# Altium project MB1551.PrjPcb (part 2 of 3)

## Sheet MEMs.SchDoc: MEMs
size A4; Date: Not used; ApprovedBy: Not used; CheckedBy: Not used; Author: Not used; CompanyName: STMicroelectronics; DrawnBy: Not used; Engineer: Not used; Organization: Not used; Address1: Not used; Address2: Not used; Address3: Not used; Address4: Not used; DocumentNumber: 12; Revision: Not used; SheetNumber: 12; SheetTotal: 16

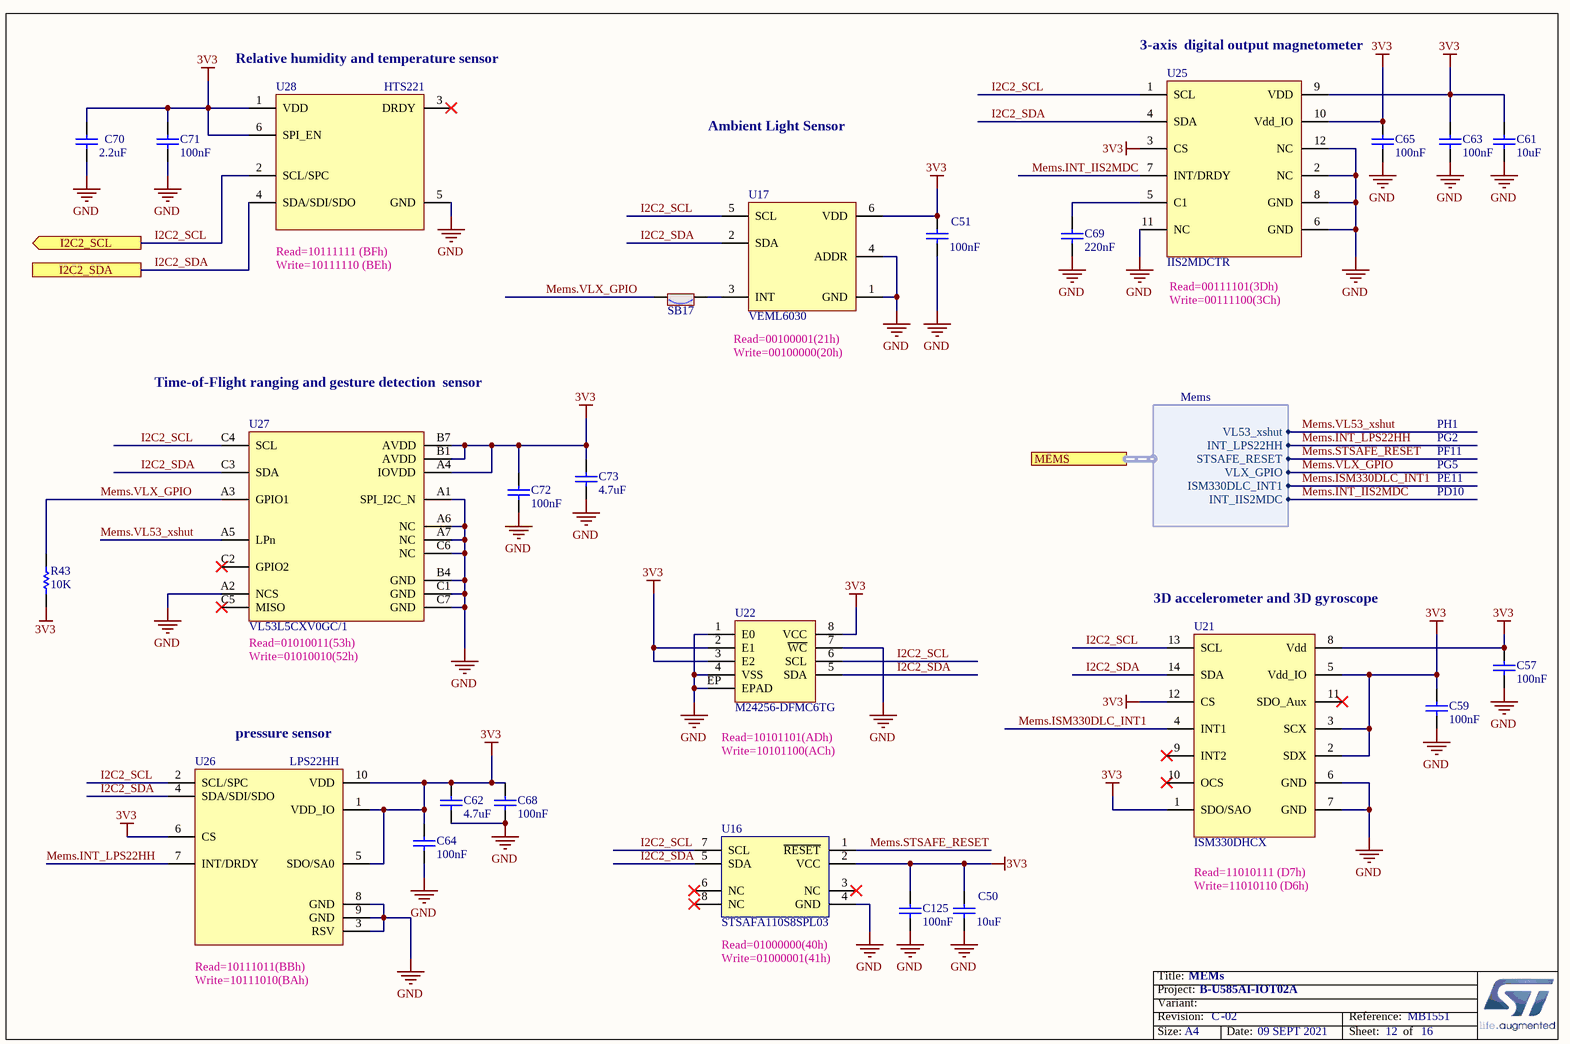
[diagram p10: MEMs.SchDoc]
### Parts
C50  value 10uF  [C0402]  (hidden comment: Capacitor)
C51  value 100nF  [C0402]
C57  value 100nF  [C0402]
C59  value 100nF  [C0402]
C61  value 10uF  [C0603]  (hidden comment: Capacitor)
C62  value 4.7uF  [C0603]  (hidden comment: Capacitor)
C63  value 100nF  [C0402]
C64  value 100nF  [C0402]
C65  value 100nF  [C0402]
C68  value 100nF  [C0402]
C69  value 220nF  [C0402]  (hidden comment: Capacitor)
C70  value 2.2uF  [C0603_H0P8]  (hidden comment: Capacitor)
C71  value 100nF  [C0402]
C72  value 100nF  [C0402]
C73  value 4.7uF  [C0603]  (hidden comment: Capacitor)
C125  value 100nF  [C0402]
R43  value 10K  [R0402]  (hidden comment: Resistor)
SB17  (no value)  [SOLDER-BRIDGE_R0603-0R]
U16  value STSAFA110S8SPL03  [ICC_SO8_5X4_P127]  (hidden comment: STSAFA110S8)
U17  VEML6030  [ICC_VISHAY_VEML6030_2X2_P065]
U21  ISM330DHCX  [ICC_LGA14_3X2P5_P050]
U22  value M24256-DFMC6TG  [ICC_DFN8-EPAD_2X3_P050]  (hidden comment: M24128-DFMC6TP)
U25  IIS2MDCTR  [ICC_LGA12_2X2_P050_H0P7]
U26  LPS22HH  [ICC_HLGA10_2X2_P050]
U27  value VL53L5CXV0GC/1  [ICC_LGA16_6P4X3_P075_H1P5]  (hidden comment: VL53L5CAV0GC)
U28  HTS221  [ICC_HLGA6_2X2_P075-1]

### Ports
I2C2_SCL (out), I2C2_SDA, MEMS (harness Mems)

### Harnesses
Mems: INT_LPS22HH, VLX_GPIO, ISM330DLC_INT1, INT_IIS2MDC, STSAFE_RESET, VL53_xshut

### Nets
3V3: C50.2 C51.1 C57.1 C59.1 C61.2 C62.2 C63.1 C64.1 C65.1 C68.1 C70.2 C71.1 C72.1 C73.2 C125.1 R43.2 U16.2(VCC) U17.6(VDD) U21.1(SDO/SAO) U21.2(SDX) U21.3(SCX) U21.5(Vdd_IO) U21.8(Vdd) U21.12(CS) U22.2(E1) U22.3(E2) U22.8(VCC) U25.3(CS) U25.9(VDD) U25.10(Vdd_IO) U26.1(VDD_IO) U26.5(SDO/SA0) U26.6(CS) U26.10(VDD) U27.A4(IOVDD) U27.B1(AVDD) U27.B7(AVDD) U28.1(VDD) U28.6(SPI_EN)
GND: C50.1 C51.2 C57.2 C59.2 C61.1 C62.1 C63.2 C64.2 C65.2 C68.2 C69.1 C70.1 C71.2 C72.2 C73.1 C125.2 U16.4(GND) U17.1(GND) U17.4(ADDR) U21.6(GND) U21.7(GND) U22.1(E0) U22.4(VSS) U22.7(~{WC}) U22.EP(EPAD) U25.2(NC) U25.6(GND) U25.8(GND) U25.11(NC) U25.12(NC) U26.3(RSV) U26.8(GND) U26.9(GND) U27.A1(SPI_I2C_N) U27.A2(NCS) U27.A6(NC) U27.A7(NC) U27.B4(GND) U27.C1(GND) U27.C6(NC) U27.C7(GND) U28.5(GND)
I2C2_SCL: U16.7(SCL) U17.5(SCL) U21.13(SCL) U22.6(SCL) U25.1(SCL) U26.2(SCL/SPC) U27.C4(SCL) U28.2(SCL/SPC) ; port I2C2_SCL
I2C2_SDA: U16.5(SDA) U17.2(SDA) U21.14(SDA) U22.5(SDA) U25.4(SDA) U26.4(SDA/SDI/SDO) U27.C3(SDA) U28.4(SDA/SDI/SDO) ; port I2C2_SDA
Mems.INT_IIS2MDC: U25.7(INT/DRDY) ; port MEMS.INT_IIS2MDC
Mems.INT_LPS22HH: U26.7(INT/DRDY) ; port MEMS.INT_LPS22HH
Mems.ISM330DLC_INT1: U21.4(INT1) ; port MEMS.ISM330DLC_INT1
Mems.STSAFE_RESET: U16.1(~{RESET}) ; port MEMS.STSAFE_RESET
Mems.VL53_xshut: U27.A5(LPn) ; port MEMS.VL53_xshut
Mems.VLX_GPIO: R43.1 SB17.2 U27.A3(GPIO1) ; port MEMS.VLX_GPIO
NetC69_2: C69.2 U25.5(C1)
NetSB17_1: SB17.1 U17.3(INT)

Not connected (* = marked no-connect by the designer): U16 3(NC)* 6(NC)* 8(NC)*; U21 9(INT2)* 10(OCS)* 11(SDO_Aux)*; U27 C2(GPIO2)* C5(MISO)*; U28 3(DRDY)*

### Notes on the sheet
- (near U25) 3-axis  digital output magnetometer
- (near U28) Relative humidity and temperature sensor
- Ambient Light Sensor
- (near U28) Read=10111111 (BFh)
  Write=10111110 (BEh)
- (near U25) Read=00111101(3Dh)
  Write=00111100(3Ch)
- Time-of-Flight ranging and gesture detection  sensor
- Read=00100001(21h)
  Write=00100000(20h)
- PG2
- PF11
- PH1
- PE11
- PD10
- PG5
- (near U27) Read=01010011(53h)
  Write=01010010(52h)
- (near U21) 3D accelerometer and 3D gyroscope
- (near U26) pressure sensor
- (near U22) Read=10101101(ADh)
  Write=10101100(ACh)
- Read=11010111 (D7h)
  Write=11010110 (D6h)
- (near U26) Read=10111011(BBh)
  Write=10111010(BAh)
- Read=01000000(40h)
  Write=01000001(41h)

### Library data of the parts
C50 = MCD-01716: Capacitor, MLCC, 10uF, 6V3, X5R, +/-20%, 0402, T=0.5mm; Part_Preference: Recommended; Manufacturer: YAGEO; Manufacturer_Part_Number: CC0402MRX5R5BB106
C51 C57 C59 C63-C65 C68 C71 C72 C125 = MCD-00006: Capacitor, MLCC, 100nF, 16V, X7R, 10%, 0402, T=0.5mm; Manufacturer_Part_Number: CC0402KRX7R7BB104; Manufacturer: YAGEO; Provided_By: Subcon; Initial_Board_Reference: MB1274
C61 = MCD-01124: Capacitor, MLCC, 10µF, 10V, X5R, 10%, 0603, T=0.8mm; Manufacturer_Part_Number: GRM188R61A106KAAL; Manufacturer: MURATA; Provided_By: SUBCO
C62 C73 = MCD-00009: Capacitor, MLCC, 4.7uF, 16V, X5R, 10%, 0603, T=0.8mm; Manufacturer_Part_Number: CC0603KRX5R7BB475; Manufacturer: YAGEO; Provided_By: subcon; Initial_Board_Reference: MB1274
C69 = MCD-00602: Capacitor, MLCC, 220nF, 16V, 0402, X7R, 10%, T=0,5mm; Manufacturer_Part_Number: GRM155R71C223KA01J; Manufacturer: MURATA; Provided_By: SUBCO
C70 = MCD-01540: Capacitor,X5R,2.2uF, 15%, 50V, 0603; Manufacturer_Part_Number: GRM188R61H225KE11; Manufacturer: MURATA; Provided_By: SUBCO
R43 = MCD-00053: Resistor,10K,0402,1%,1/16W; Manufacturer_Part_Number: RC0402FR-0710KL; Manufacturer: YAGEO; Provided_By: SUBCO
SB17 = MCD-00071: Solder Bridge ON; Part_Type: Mechanical; Provided_By: Subcon; Initial_Board_Reference: mb1274
U16 = MCD-02399: Authentication, state-of-the-art security for peripherals and IoT devices; Part_Type: IC; Part_Preference: Recommended; Manufacturer: STMICROELECTRONICS
U17 = MCD-02336: High Accuracy Ambient Light Sensor with I2C Interface; Part_Type: IC; Part_Preference: Recommended; Manufacturer: VISHAY
U21 = MCD-02160: iNEMO inertial module: 3D accelerometer and 3D gyroscope, with digital output for industrial applications; Part_Preference: Recommended; Part_Type: IC; Manufacturer: STMICROELECTRONICS; Order_code_RS: ISM330DHCXTR; Component_Country_Of_Origin: Malta, Philippines
U22 = MCD-01871: I2C Memory 3V3, 256Kbits, 2x3,0.55mm, UFDFPN8; Part_Type: IC; Manufacturer: STMICROELECTRONICS; BMS_Part_Number: 9175665; Provided_By: SUBCO with ST control
U25 = MCD-01713: High-accuracy, ultra-low-power, 3-axis, digital output magnetometer; Part_Type: IC; Manufacturer: STMICROELECTRONICS; Provided_By: SUBCO with ST control
U26 = MCD-01702: High-performance MEMS nano pressure sensor:260-1260 hPa absolute digital output barometer; Part_Type: IC; Manufacturer: STMICROELECTRONICS; Provided_By: SUBCO
U27 = MCD-02257: Time-of-Flight mini depth camera; Part_Type: IC; Part_Preference: Recommended; Manufacturer: STMICROELECTRONICS; Manufacturer_HQ_COO: EU
U28 = MCD-01447: Capacitive digital sensor for relative humidity and temperature; Part_Type: IC; Manufacturer: STMICROELECTRONICS; BMS_Part_Number: 9188011; ECCN_US: EAR99; ECCN_EU: NEC; Provided_By: SUBCO

## Sheet OCTOSPI.SchDoc: OCTOSPI
size A4; Date: Not used; ApprovedBy: Not used; CheckedBy: Not used; Author: Not used; CompanyName: STMicroelectronics; DrawnBy: Not used; Engineer: Not used; Organization: Not used; Address1: Not used; Address2: Not used; Address3: Not used; Address4: Not used; DocumentNumber: 6; Revision: Not used; SheetNumber: 6; SheetTotal: 16

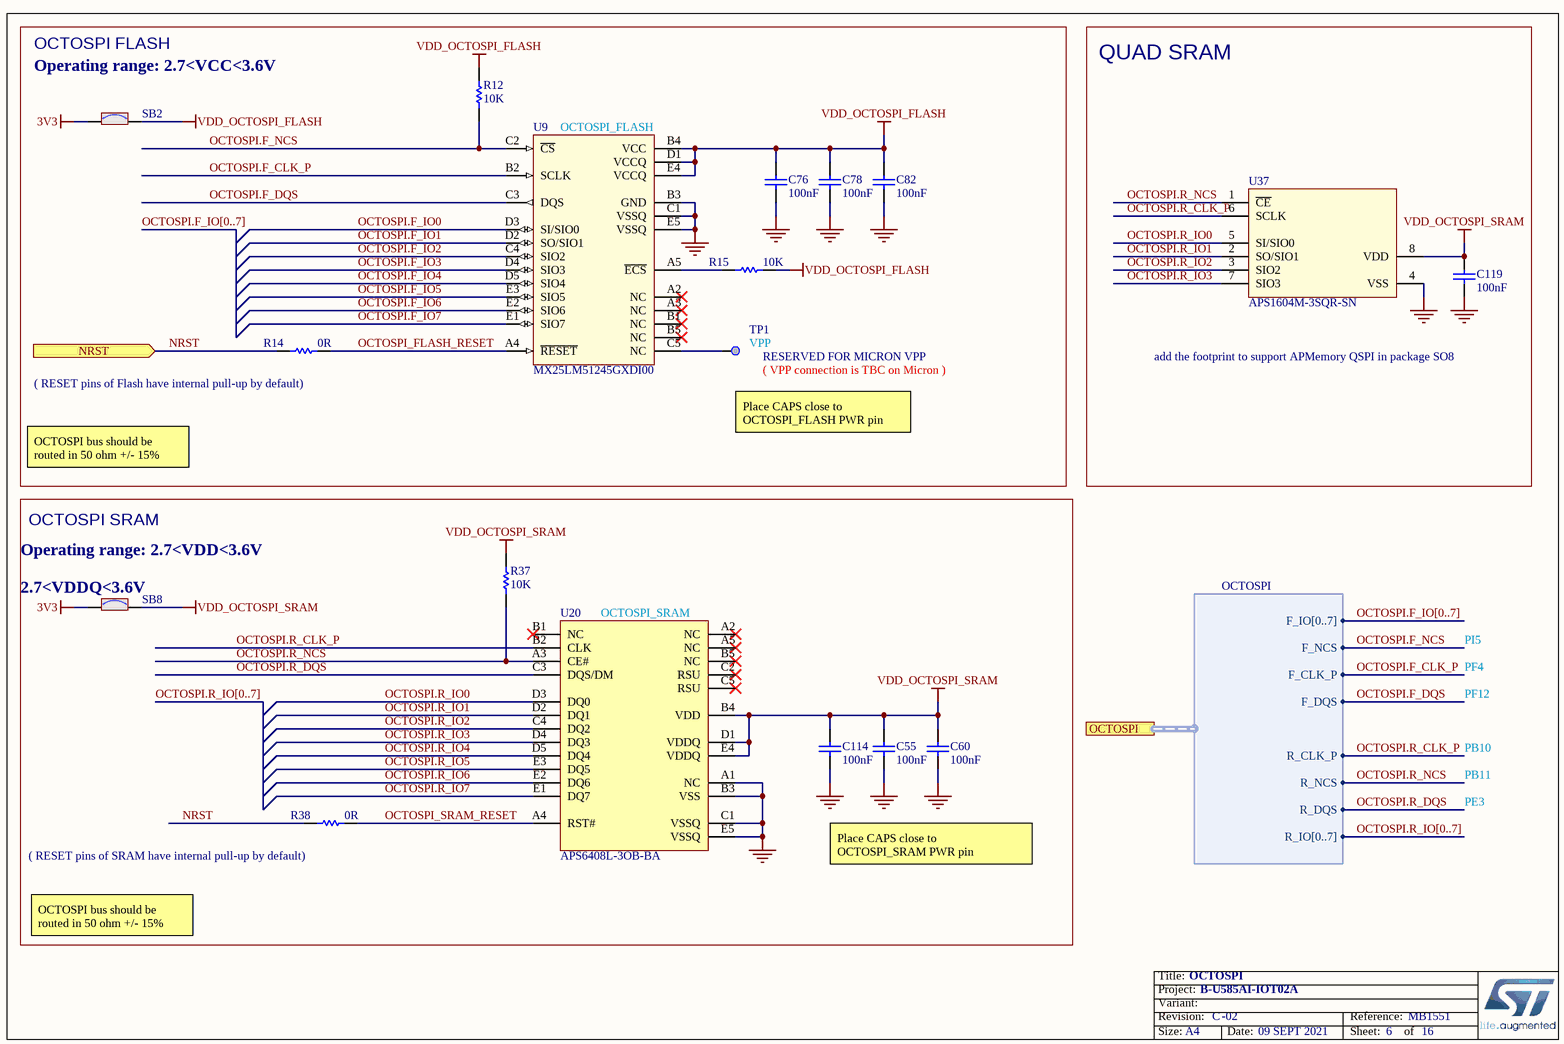
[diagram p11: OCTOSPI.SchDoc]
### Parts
C55  value 100nF  [C0402]
C60  value 100nF  [C0402]
C76  value 100nF  [C0402]
C78  value 100nF  [C0402]
C82  value 100nF  [C0402]
C114  value 100nF  [C0402]
C119  value 100nF  [C0402]  (hidden comment: Capacitor)
R12  value 10K  [R0603]
R14  value 0R  [R0603]
R15  value 10K  [R0603]
R37  value 10K  [R0603]
R38  value 0R  [R0603]
SB2  (no value)  [SOLDER-BRIDGE_R0603-0R]
SB8  (no value)  [SOLDER-BRIDGE_R0603-0R]
TP1  value VPP  [TP_SMD_1MM]  (no BOM)
U9  value MX25LM51245GXDI00  [ICC_BGA24_5X5-BALL-ARRAY_6X8_P1]
U20  value APS6408L-3OB-BA  [ICC_MINI-BGA24_6X8_P1]  (hidden comment: APS6408L-xOB)
U37  APS1604M-3SQR-SN  [ICC_SO8_5X4_P127]

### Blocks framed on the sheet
OCTOSPI FLASH: C76 C78 C82 R12 R14 R15 SB2 TP1 U9
QUAD SRAM: C119 U37
OCTOSPI SRAM: C55 C60 C114 R37 R38 SB8 U20

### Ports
NRST (in), OCTOSPI (harness OCTOSPI)

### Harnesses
OCTOSPI: F_DQS, F_CLK_P, F_NCS, R_CLK_P, R_NCS, R_DQS, R_IO[0..7], F_IO[0..7]

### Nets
3V3: SB2.1 SB8.1
GND: C55.1 C60.1 C76.1 C78.1 C82.1 C114.1 C119.1 U9.B3(GND) U9.C1(VSSQ) U9.E5(VSSQ) U20.A1(NC) U20.B3(VSS) U20.C1(VSSQ) U20.E5(VSSQ) U37.4(VSS)
VDD_OCTOSPI_FLASH: C76.2 C78.2 C82.2 R12.2 R15.1 SB2.2 U9.B4(VCC) U9.D1(VCCQ) U9.E4(VCCQ)
VDD_OCTOSPI_SRAM: C55.2 C60.2 C114.2 C119.2 R37.2 SB8.2 U20.B4(VDD) U20.D1(VDDQ) U20.E4(VDDQ) U37.8(VDD)
NRST: R14.1 R38.1 ; port NRST
OCTOSPI.F_CLK_P: U9.B2(SCLK) ; port OCTOSPI.F_CLK_P
OCTOSPI.F_DQS: U9.C3(DQS) ; port OCTOSPI.F_DQS
OCTOSPI.F_IO0: U9.D3(SI/SIO0)
OCTOSPI.F_IO1: U9.D2(SO/SIO1)
OCTOSPI.F_IO2: U9.C4(SIO2)
OCTOSPI.F_IO3: U9.D4(SIO3)
OCTOSPI.F_IO4: U9.D5(SIO4)
OCTOSPI.F_IO5: U9.E3(SIO5)
OCTOSPI.F_IO6: U9.E2(SIO6)
OCTOSPI.F_IO7: U9.E1(SIO7)
OCTOSPI.F_NCS: R12.1 U9.C2(~{CS}) ; port OCTOSPI.F_NCS
OCTOSPI.R_CLK_P: U20.B2(CLK) U37.6(SCLK) ; port OCTOSPI.R_CLK_P
OCTOSPI.R_DQS: U20.C3(DQS/DM) ; port OCTOSPI.R_DQS
OCTOSPI.R_IO0: U20.D3(DQ0) U37.5(SI/SIO0)
OCTOSPI.R_IO1: U20.D2(DQ1) U37.2(SO/SIO1)
OCTOSPI.R_IO2: U20.C4(DQ2) U37.3(SIO2)
OCTOSPI.R_IO3: U20.D4(DQ3) U37.7(SIO3)
OCTOSPI.R_IO4: U20.D5(DQ4)
OCTOSPI.R_IO5: U20.E3(DQ5)
OCTOSPI.R_IO6: U20.E2(DQ6)
OCTOSPI.R_IO7: U20.E1(DQ7)
OCTOSPI.R_NCS: R37.1 U20.A3(CE#) U37.1(~{CE}) ; port OCTOSPI.R_NCS
OCTOSPI_FLASH_RESET: R14.2 U9.A4(~{RESET})
OCTOSPI_SRAM_RESET: R38.2 U20.A4(RST#)
NetR15_2: R15.2 U9.A5(~{ECS})
NetTP1_1: TP1.1 U9.C5(NC)

Not connected (* = marked no-connect by the designer): U9 A2(NC)* A3(NC)* B1(NC)* B5(NC)*; U20 A2(NC)* A5(NC)* B1(NC)* B5(NC)* C2(RSU)* C5(RSU)*

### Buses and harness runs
bus OCTOSPI.F_IO[0..7]
bus OCTOSPI.R_IO[0..7]

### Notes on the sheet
- (near SB2) Operating range: 2.7<VCC<3.6V
  2.7<VCCQ<3.6V
- (near U9) OCTOSPI_FLASH
- (near R14) ( RESET pins of Flash have internal pull-up by default)
- (near TP1) ( VPP connection is TBC on Micron )
- (near TP1) RESERVED FOR MICRON VPP
- add the footprint to support APMemory QSPI in package SO8
- (near TP1) Place CAPS close to OCTOSPI_FLASH PWR pin
- OCTOSPI bus should be routed in 50 ohm +/- 15%
- (near SB8) Operating range: 2.7<VDD<3.6V
  2.7<VDDQ<3.6V
- (near U20) OCTOSPI_SRAM
- PI5
- PF12
- PF4
- PB10
- PB11
- (near R38) ( RESET pins of SRAM have internal pull-up by default)
- Place CAPS close to OCTOSPI_SRAM PWR pin
- PE3

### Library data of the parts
C55 C60 C76 C78 C82 C114 = MCD-00102: Capacitor, MLCC, 100nF, 16V, X7R, 10%, 0402, T=0,5mm; Manufacturer_Part_Number: CC0402KRX7R7BB104; Manufacturer: YAGEO; Alternate_Manufacturer_Part_Number: GCM155R71C104KA55D; Alternate_Manufacturer: MURATA; Provided_By: SUBCO
C119 = MCD-00006: Capacitor, MLCC, 100nF, 16V, X7R, 10%, 0402, T=0.5mm; Manufacturer_Part_Number: CC0402KRX7R7BB104; Manufacturer: YAGEO; Alternate_Manufacturer_Part_Number: GCM155R71C104KA55D; Alternate_Manufacturer: MURATA; Provided_By: SUBCO; ECCN_US: EAR99; ECCN_EU: NEC
R12 R15 R37 = MCD-00220: Resistor,10K,0603,1%,1/10W; Manufacturer_Part_Number: RC0603FR-0710KL; Manufacturer: YAGEO; Provided_By: Subcon; Initial_Board_Reference: MB1319
R14 R38 = MCD-00056: Resistor,0R,0603,5%,1/10W; Manufacturer_Part_Number: RC0603JR-070RL; Manufacturer: YAGEO; Provided_By: subcon; Initial_Board_Reference: MB1274
SB2 SB8 = MCD-00071: Solder Bridge ON; Part_Type: Mechanical; Provided_By: Subcon; Initial_Board_Reference: MB1274
TP1 = MCD-00074: Test Point 1mm; Part_Type: Mechanical; Initial_Board_Reference: MB1274
U9 = MCD-00246: Memory,Octo-SPI-NOR,512Mb,2048x16,133MHz,3V,DTR,BGA24, CMOS MXSMIO; Part_Type: IC; Manufacturer: MACRONIX; Provided_By: STM; Initial_Board_Reference: MB1331; ECCN_US: TBD; Remark: lead time = 16 weeks
U20 = MCD-01391: Memory, DDR Octal SPI PSRAM, 64Mb, 8Mx8, up to 133MHz@3V0, 104MHz@3V3, PASR; Part_Type: IC; Manufacturer: APMEMORY; BMS_Part_Number: 9171982; ECCN_US: 3A991B2B; Provided_By: SUBCO
U37 = MCD-01790: Quad-SPI PSRAM APS1604M-3SQR-SN with SOP-8L package; Part_Type: IC; Manufacturer: APMEMORY; Provided_By: SUBCO

## Sheet STMod+.SchDoc: STMod+
size A4; Author: P.A.; CompanyName: STMicroelectronics; Organization: Microcontrollers Division; Address1: 12, Rue Jules HOROWITZ; Address2: 38019 Grenoble; Address3: FRANCE; DocumentNumber: 7; Revision: C; SheetNumber: 7; SheetTotal: 16; Project: STM32L4S5AII6_IOT_V2

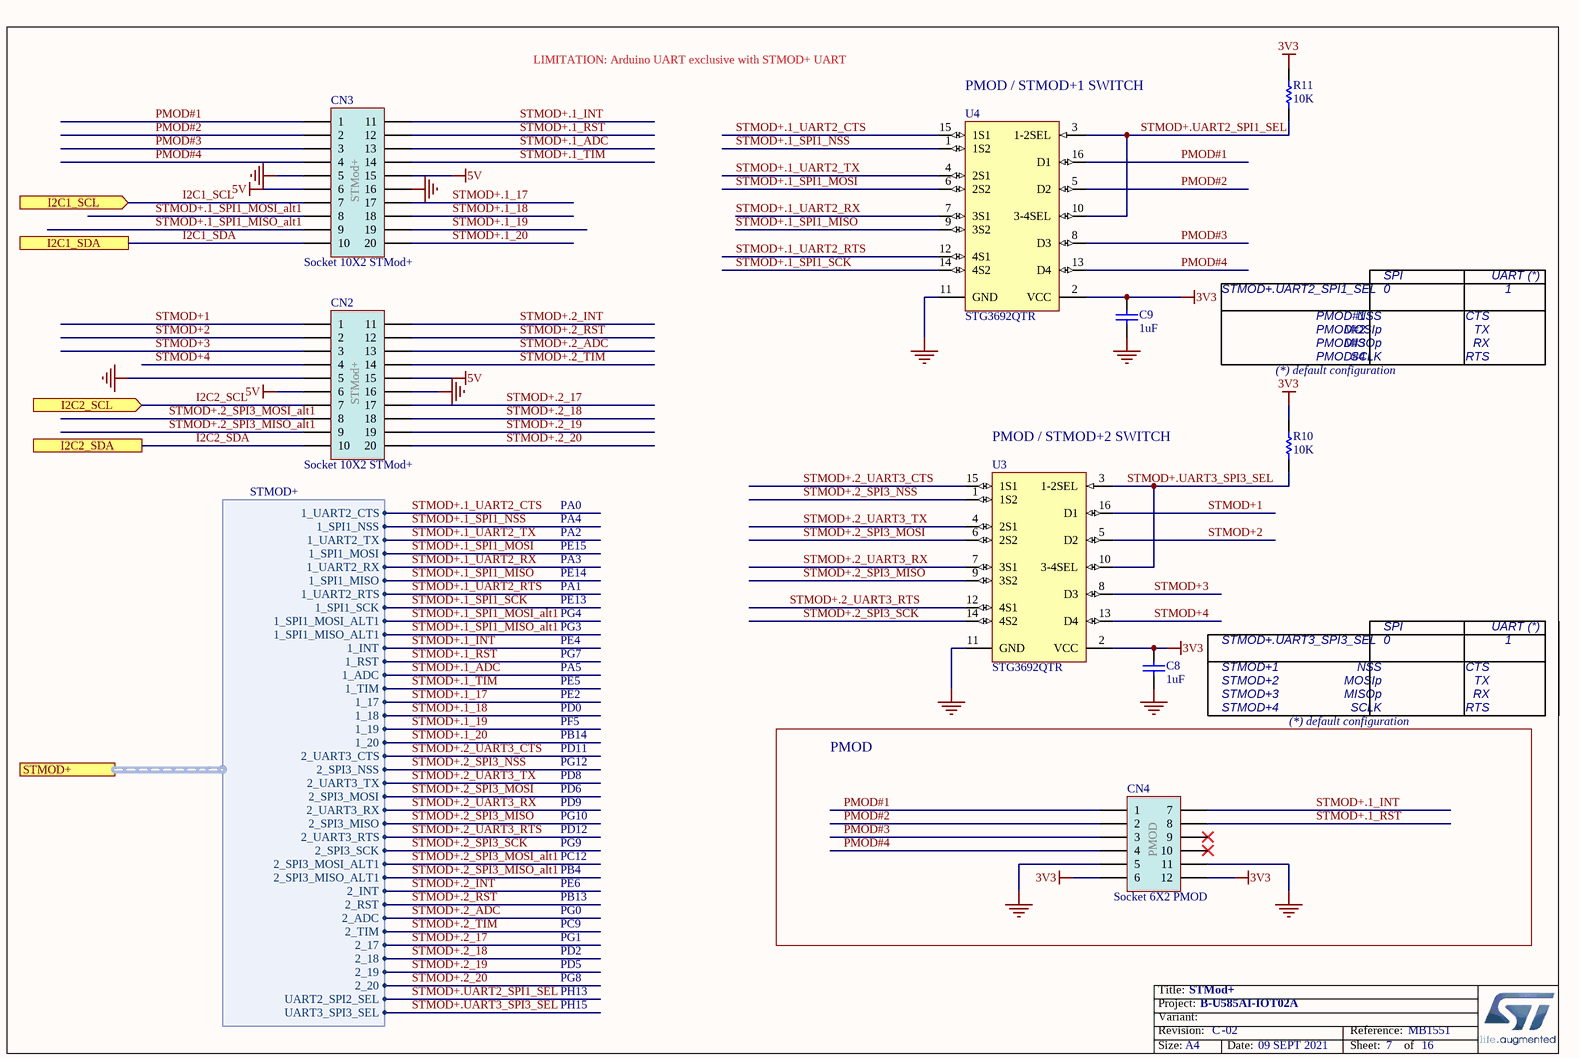
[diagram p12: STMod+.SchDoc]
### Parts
C8  value 1uF  [C0603]  (hidden comment: Capacitor)
C9  value 1uF  [C0603]  (hidden comment: Capacitor)
CN2  Socket 10X2 STMod+  [CON_SAMTEC_SQT-110-01-F-D-RA__STMOD+]
CN3  Socket 10X2 STMod+  [CON_SAMTEC_SQT-110-01-F-D-RA__STMOD+]
CN4  Socket 6X2 PMOD  [CON_SAMTEC_SSW-106-02-F-D-RA__PMOD]
R10  value 10K  [R0402]
R11  value 10K  [R0402]
U3  STG3692QTR  [ICC_UFQFN16-EPAD_2P6X1P8_P040]
U4  STG3692QTR  [ICC_UFQFN16-EPAD_2P6X1P8_P040]

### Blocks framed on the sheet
PMOD: CN4

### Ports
I2C1_SCL (in), I2C1_SDA, I2C2_SCL (in), I2C2_SDA, STMOD+ (harness STMOD+)

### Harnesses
STMOD+: 1_UART2_CTS, 1_SPI1_NSS, 1_UART2_TX, 1_SPI1_MOSI, 1_SPI1_MISO, 1_UART2_RTS, 1_ADC, 1_17, 1_18, 1_19, 1_20, 2_UART3_CTS, 2_SPI3_NSS, 2_UART3_TX, 2_SPI3_MOSI, 2_SPI3_MISO, 2_UART3_RTS, 2_UART3_RX, 1_UART2_RX, 1_SPI1_MOSI_ALT1, 2_SPI3_SCK, 2_SPI3_MOSI_ALT1, 1_SPI1_MISO_ALT1, 1_SPI1_SCK, 1_RST, 1_INT, 1_TIM, 2_SPI3_MISO_ALT1, 2_INT, 2_RST, 2_ADC, 2_TIM, 2_17, 2_18, 2_19, 2_20, UART2_SPI2_SEL, UART3_SPI3_SEL

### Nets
3V3: C8.2 C9.2 CN4.6 CN4.12 R10.2 R11.2 U3.2(VCC) U4.2(VCC)
5V: CN2.6 CN2.15 CN3.6 CN3.15
GND: C8.1 C9.1 CN2.5 CN2.16 CN3.5 CN3.16 CN4.5 CN4.11 U3.11(GND) U4.11(GND)
I2C1_SCL: CN3.7 ; port I2C1_SCL
I2C1_SDA: CN3.10 ; port I2C1_SDA
I2C2_SCL: CN2.7 ; port I2C2_SCL
I2C2_SDA: CN2.10 ; port I2C2_SDA
PMOD#1: CN3.1 CN4.1 U4.16(D1)
PMOD#2: CN3.2 CN4.2 U4.5(D2)
PMOD#3: CN3.3 CN4.3 U4.8(D3)
PMOD#4: CN3.4 CN4.4 U4.13(D4)
STMOD+1: CN2.1 U3.16(D1)
STMOD+2: CN2.2 U3.5(D2)
STMOD+3: CN2.3 U3.8(D3)
STMOD+4: CN2.4 U3.13(D4)
STMOD+.1_17: CN3.17 ; port STMOD+.1_17
STMOD+.1_18: CN3.18 ; port STMOD+.1_18
STMOD+.1_19: CN3.19 ; port STMOD+.1_19
STMOD+.1_20: CN3.20 ; port STMOD+.1_20
STMOD+.1_ADC: CN3.13 ; port STMOD+.1_ADC
STMOD+.1_INT: CN3.11 CN4.7 ; port STMOD+.1_INT
STMOD+.1_RST: CN3.12 CN4.8 ; port STMOD+.1_RST
STMOD+.1_SPI1_MISO: U4.9(3S2) ; port STMOD+.1_SPI1_MISO  [project net ARD.D12_SPI1_MISO]
STMOD+.1_SPI1_MISO_alt1: CN3.9 ; port STMOD+.1_SPI1_MISO_ALT1
STMOD+.1_SPI1_MOSI: U4.6(2S2) ; port STMOD+.1_SPI1_MOSI  [project net ARD.D11_TIM_SPI1_MOSI]
STMOD+.1_SPI1_MOSI_alt1: CN3.8 ; port STMOD+.1_SPI1_MOSI_ALT1
STMOD+.1_SPI1_NSS: U4.1(1S2) ; port STMOD+.1_SPI1_NSS
STMOD+.1_SPI1_SCK: U4.14(4S2) ; port STMOD+.1_SPI1_SCK  [project net ARD.D13_SPI1_SCK]
STMOD+.1_TIM: CN3.14 ; port STMOD+.1_TIM
STMOD+.1_UART2_CTS: U4.15(1S1) ; port STMOD+.1_UART2_CTS
STMOD+.1_UART2_RTS: U4.12(4S1) ; port STMOD+.1_UART2_RTS
STMOD+.1_UART2_RX: U4.7(3S1) ; port STMOD+.1_UART2_RX
STMOD+.1_UART2_TX: U4.4(2S1) ; port STMOD+.1_UART2_TX
STMOD+.2_17: CN2.17 ; port STMOD+.2_17
STMOD+.2_18: CN2.18 ; port STMOD+.2_18
STMOD+.2_19: CN2.19 ; port STMOD+.2_19
STMOD+.2_20: CN2.20 ; port STMOD+.2_20
STMOD+.2_ADC: CN2.13 ; port STMOD+.2_ADC
STMOD+.2_INT: CN2.11 ; port STMOD+.2_INT
STMOD+.2_RST: CN2.12 ; port STMOD+.2_RST
STMOD+.2_SPI3_MISO: U3.9(3S2) ; port STMOD+.2_SPI3_MISO
STMOD+.2_SPI3_MISO_alt1: CN2.9 ; port STMOD+.2_SPI3_MISO_ALT1
STMOD+.2_SPI3_MOSI: U3.6(2S2) ; port STMOD+.2_SPI3_MOSI
STMOD+.2_SPI3_MOSI_alt1: CN2.8 ; port STMOD+.2_SPI3_MOSI_ALT1
STMOD+.2_SPI3_NSS: U3.1(1S2) ; port STMOD+.2_SPI3_NSS
STMOD+.2_SPI3_SCK: U3.14(4S2) ; port STMOD+.2_SPI3_SCK
STMOD+.2_TIM: CN2.14 ; port STMOD+.2_TIM
STMOD+.2_UART3_CTS: U3.15(1S1) ; port STMOD+.2_UART3_CTS
STMOD+.2_UART3_RTS: U3.12(4S1) ; port STMOD+.2_UART3_RTS
STMOD+.2_UART3_RX: U3.7(3S1) ; port STMOD+.2_UART3_RX  [project net ARD.D0_RX]
STMOD+.2_UART3_TX: U3.4(2S1) ; port STMOD+.2_UART3_TX  [project net ARD.D1_TX]
STMOD+.UART2_SPI1_SEL: R11.1 U4.3(1-2SEL) U4.10(3-4SEL) ; port STMOD+.UART2_SPI2_SEL
STMOD+.UART3_SPI3_SEL: R10.1 U3.3(1-2SEL) U3.10(3-4SEL) ; port STMOD+.UART3_SPI3_SEL

Not connected (* = marked no-connect by the designer): CN4 9* 10*

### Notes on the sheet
- LIMITATION: Arduino UART exclusive with STMOD+ UART
- (near U4) PMOD / STMOD+1 SWITCH
- STMOD+.UART2_SPI1_SEL
- PMOD#2
- PMOD#1
- 0
- MOSIp
- SPI
- NSS
- TX
- UART (*)
- CTS
- 1
- (*) default configuration
- PMOD#3
- PMOD#4
- MISOp
- SCLK
- RX
- RTS
- (near U3) PMOD / STMOD+2 SWITCH
- PA0
- PA4
- PA2
- PE14
- PA3
- PE15
- PA1
- PE13
- PG3
- PG4
- PE4
- PA5
- PG7
- STMOD+.UART3_SPI3_SEL
- STMOD+1
- PE5
- PE2
- PD0
- PF5
- PB14
- STMOD+2
- STMOD+3
- STMOD+4
- PD11
- PG12
- PD8
- PD9
- PD6
- PG10
- PD12
- PG9
- PC12
- PB4
- PE6
- PG0
- PC9
- PB13
- PG1
- PD2
- PG8
- PD5
- PH13
- PH15

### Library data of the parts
C8 C9 = MCD-00010: Capacitor, MLCC, 1uF, 16V, X5R, 10%, 0603, T=0,8mm; Manufacturer_Part_Number: CC0603KRX5R7BB105; Manufacturer: YAGEO; Provided_By: SUBCO; Initial_Board_Reference: MB1274; Item Type: Item; Path: ws/MCD_ApplicationBoards/Lists/MCDPARTSdatabase
CN2 CN3 = MCD-00309: Socket 10x2, 2.00mm, RA, TH, Height 6.35mm/2.29mm; Part_Type: Connector; Manufacturer_Part_Number: SQT-110-01-F-D-RA; Manufacturer: SAMTEC; Provided_By: SubCon; Initial_Board_Reference: MB1311
CN4 = MCD-00308: Socket, 6x2, 2.54mm, TH, RA, Height 8.51mm/7.62mm; Part_Type: Connector; Manufacturer_Part_Number: SSW-106-02-F-D-RA; Manufacturer: SAMTEC; Provided_By: Subcon; Initial_Board_Reference: MB1311
R10 R11 = MCD-00053: Resistor,10K,0402,1%,1/16W; Manufacturer_Part_Number: RC0402FR-0710KL; Manufacturer: YAGEO; Provided_By: subcon; Initial_Board_Reference: MB1274
U3 U4 = MCD-00317: Low voltage high bandwidth quad SPDT switch; Part_Type: IC; Manufacturer: STMICROELECTRONICS; Provided_By: SUBCO with ST control; Initial_Board_Reference: MB1311; Item Type: Item; Path: ws/MCD_ApplicationBoards/Lists/MCDPARTSdatabase

## Sheet ST_LINK_V3E.SchDoc: ST_LINK_V3E
size A3; Date: Not used; ApprovedBy: Not used; CheckedBy: Not used; Author: Not used; CompanyName: STMicroelectronics; DrawnBy: Not used; Engineer: Not used; Organization: Not used; Address1: Not used; Address2: Not used; Address3: Not used; Address4: Not used; DocumentNumber: 15; Revision: Not used; SheetNumber: 15; SheetTotal: 16

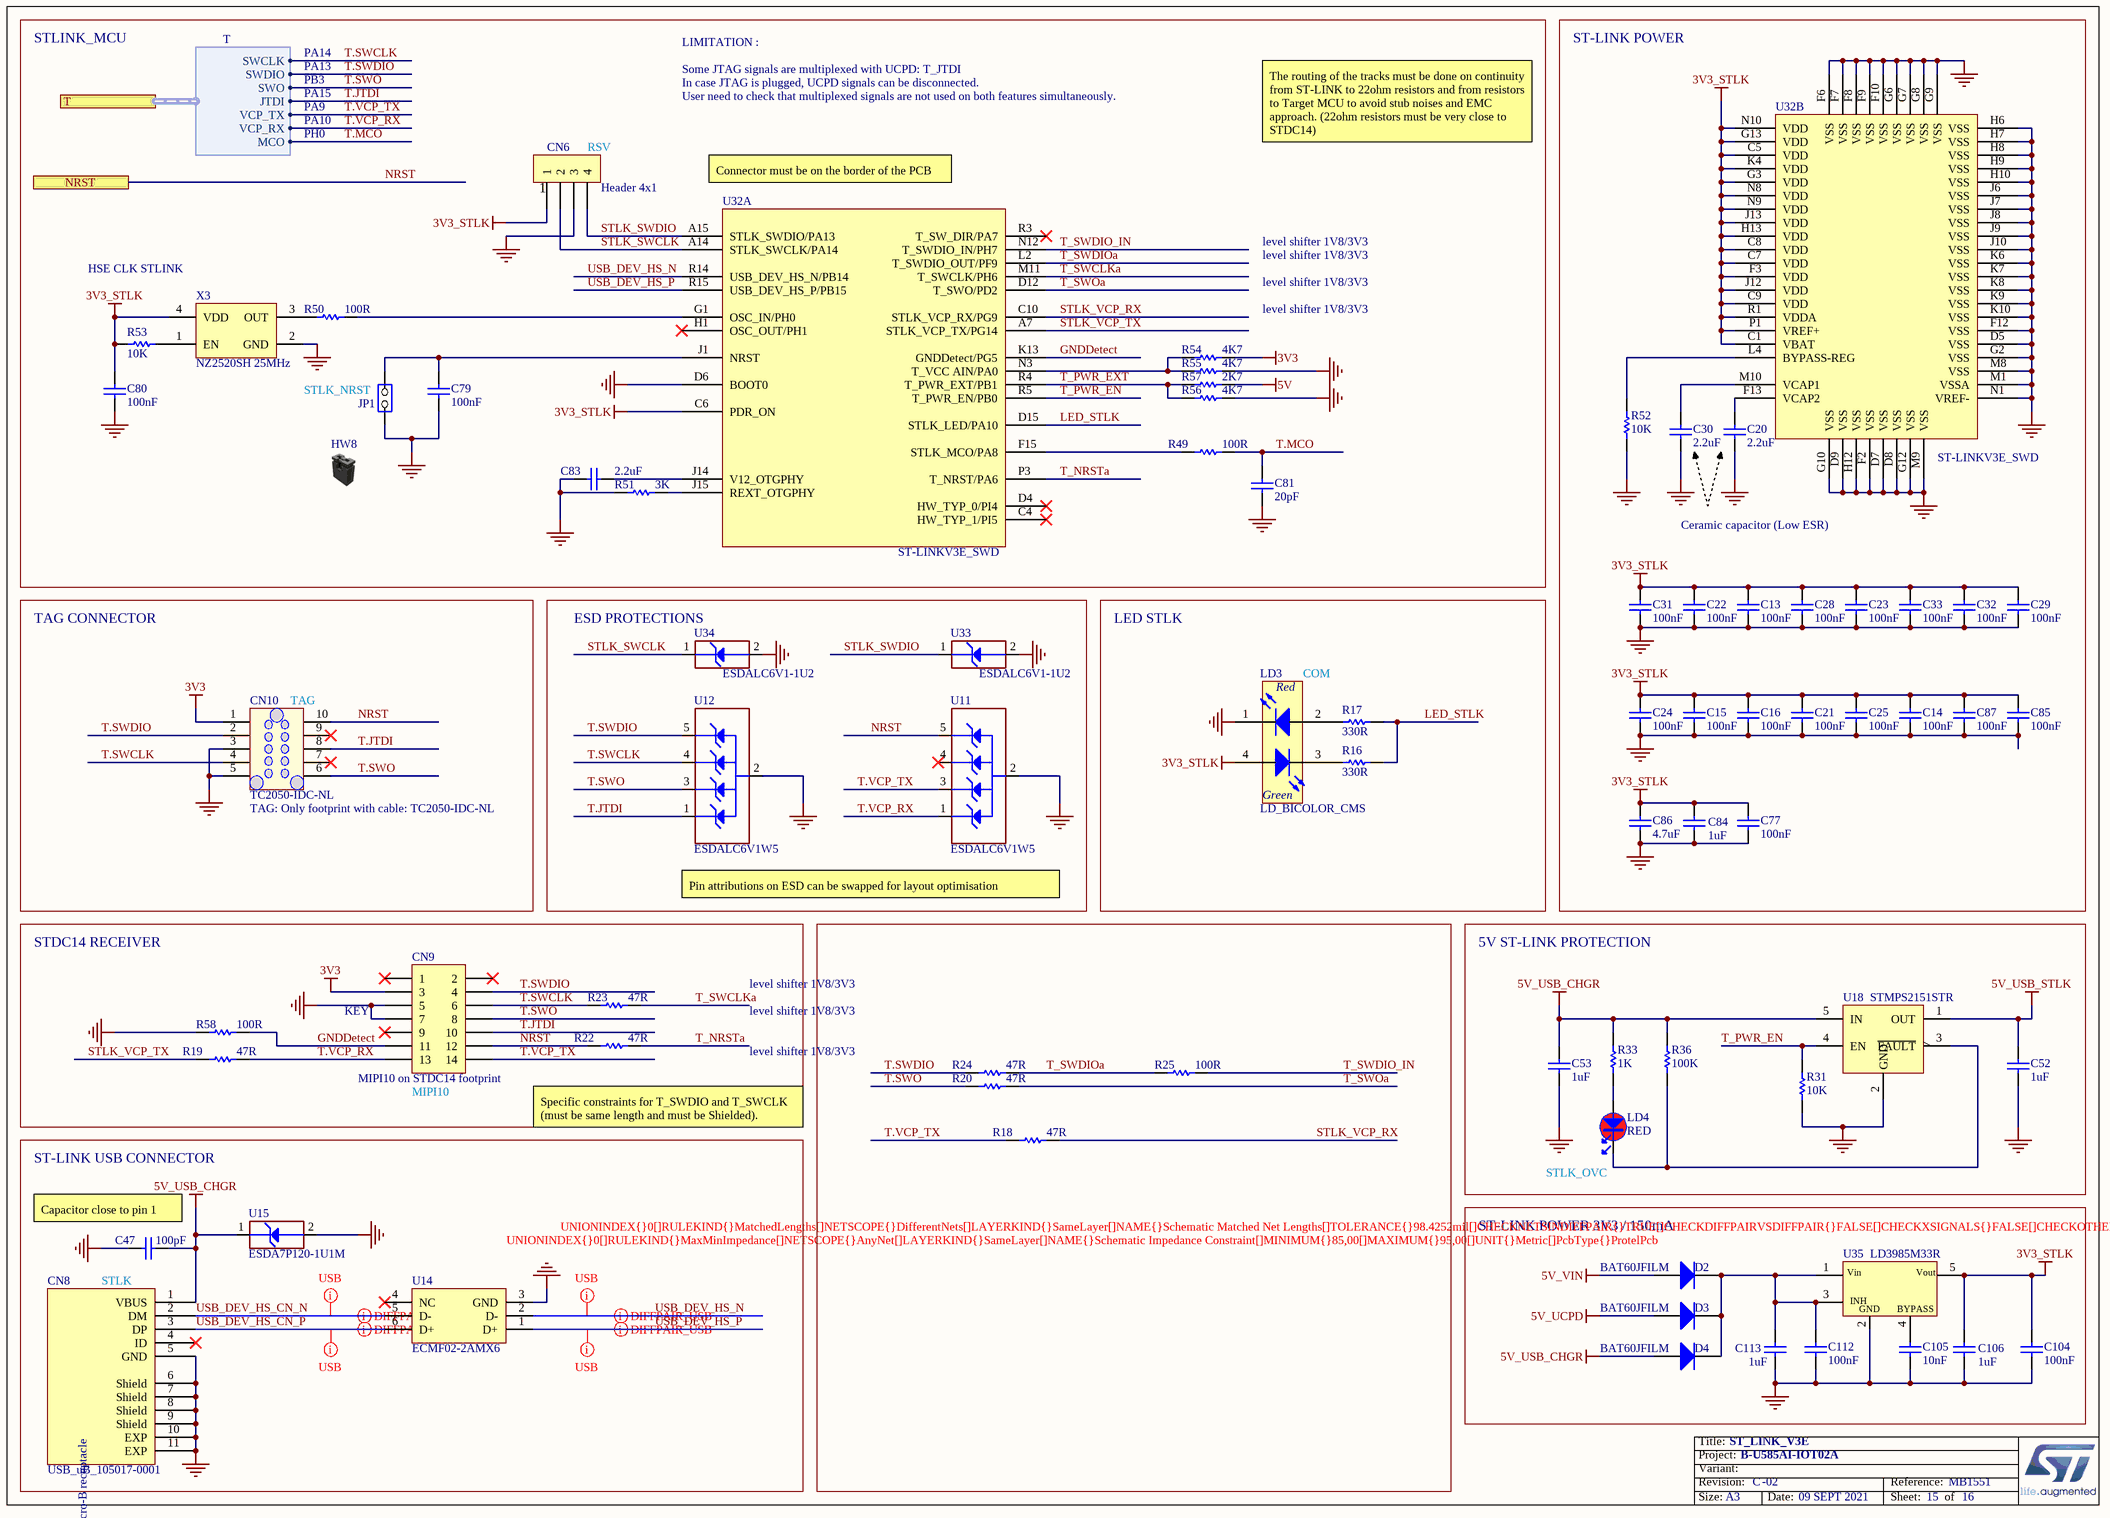
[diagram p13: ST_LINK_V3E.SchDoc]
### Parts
C13  value 100nF  [C0402]  (hidden comment: Capacitor)
C14  value 100nF  [C0402]  (hidden comment: Capacitor)
C15  value 100nF  [C0402]  (hidden comment: Capacitor)
C16  value 100nF  [C0402]  (hidden comment: Capacitor)
C20  value 2.2uF  [C0603]  (hidden comment: Capacitor)
C21  value 100nF  [C0402]  (hidden comment: Capacitor)
C22  value 100nF  [C0402]  (hidden comment: Capacitor)
C23  value 100nF  [C0402]  (hidden comment: Capacitor)
C24  value 100nF  [C0402]  (hidden comment: Capacitor)
C25  value 100nF  [C0402]  (hidden comment: Capacitor)
C28  value 100nF  [C0402]  (hidden comment: Capacitor)
C29  value 100nF  [C0402]  (hidden comment: Capacitor)
C30  value 2.2uF  [C0603]  (hidden comment: Capacitor)
C31  value 100nF  [C0402]  (hidden comment: Capacitor)
C32  value 100nF  [C0402]  (hidden comment: Capacitor)
C33  value 100nF  [C0402]  (hidden comment: Capacitor)
C47  value 100pF  [C0402]  (hidden comment: Capacitor)
C52  value 1uF  [C0603]  (hidden comment: Capacitor)
C53  value 1uF  [C0603]  (hidden comment: Capacitor)
C77  value 100nF  [C0402]  (hidden comment: Capacitor)
C79  value 100nF  [C0402]  (hidden comment: Capacitor)
C80  value 100nF  [C0402]  (hidden comment: Capacitor)
C81  value 20pF  [C0402]  (hidden comment: Capacitor)
C83  value 2.2uF  [C0603]  (hidden comment: Capacitor)
C84  value 1uF  [C0603]  (hidden comment: Capacitor)
C85  value 100nF  [C0402]  (hidden comment: Capacitor)
C86  value 4.7uF  [C0603]  (hidden comment: Capacitor)
C87  value 100nF  [C0402]  (hidden comment: Capacitor)
C104  value 100nF  [C0402]  (hidden comment: Capacitor)
C105  value 10nF  [C0402]  (hidden comment: Capacitor)
C106  value 1uF  [C0603]  (hidden comment: Capacitor)
C112  value 100nF  [C0402]  (hidden comment: Capacitor)
C113  value 1uF  [C0603]  (hidden comment: Capacitor)
CN6  Header 4x1  [CON_SAMTEC_TSW-104-07-G-S]
CN8  value USB_uB_105017-0001  [CON_USBMICROB_MOLEX_105017-0001_H2P90]  (hidden comment: USB_uB_105017.0001)
CN9  value MIPI10 on STDC14 footprint  [CON_STDC14_Receiver_MEDIUM_WITH_MIPI10_3D]  (hidden comment: Header 7x2)
CN10  value TC2050-IDC-NL  [CON_TAG-C_TC2050-IDC-NL]
D2  BAT60JFILM  [DIO_SOD323]
D3  BAT60JFILM  [DIO_SOD323]
D4  BAT60JFILM  [DIO_SOD323]
HW8  Shunt Black 2.54mm  (value not drawn)  (mechanical)
JP1  Jumper_Header 2x1  [CON_SAMTEC_TSW-102-07-G-S]  (value not drawn)
LD3  LD_BICOLOR_CMS  [LED_BI-GR_HSMF-A201-A00J1]
LD4  value RED  [LED_0603_RED]  (hidden comment: LED_red)
R16  value 330R  [R0402]  (hidden comment: Resistor)
R17  value 330R  [R0402]  (hidden comment: Resistor)
R18  value 47R  [R0402]  (hidden comment: Resistor)
R19  value 47R  [R0402]  (hidden comment: Resistor)
R20  value 47R  [R0402]  (hidden comment: Resistor)
R22  value 47R  [R0402]  (hidden comment: Resistor)
R23  value 47R  [R0402]  (hidden comment: Resistor)
R24  value 47R  [R0402]  (hidden comment: Resistor)
R25  value 100R  [R0402]  (hidden comment: Resistor)
R31  value 10K  [R0402]  (hidden comment: Resistor)
R33  value 1K  [R0402]  (hidden comment: Resistor)
R36  value 100K  [R0402]  (hidden comment: Resistor)
R49  value 100R  [R0402]  (hidden comment: Resistor)
R50  value 100R  [R0402]  (hidden comment: Resistor)
R51  value 3K  [R0402]  (hidden comment: Resistor)
R52  value 10K  [R0402]  (hidden comment: Resistor)
R53  value 10K  [R0402]  (hidden comment: Resistor)
R54  value 4K7  [R0402]  (hidden comment: Resistor)
R55  value 4K7  [R0402]  (hidden comment: Resistor)
R56  value 4K7  [R0402]  (hidden comment: Resistor)
R57  value 2K7  [R0402]  (hidden comment: Resistor)
R58  value 100R  [R0402]  (hidden comment: Resistor)
U11  ESDALC6V1W5  [ESD_SOT323-5L]
U12  ESDALC6V1W5  [ESD_SOT323-5L]
U14  ECMF02-2AMX6  [ESD_QFN-6L_1P7X1P5_P050]
U15  value ESDA7P120-1U1M  [ESD_QFN1610_2N_1K_2A]  (hidden comment: ESD-TRANSIL)
U18  STMPS2151STR  [MOS_SOT23-5L]
U32  ST-LINKV3E_SWD  [ICC_UFBGA201_176+25_10X10_P065]  (parts A,B of 2)
U33  value ESDALC6V1-1U2  [ESD_ST0201]  (hidden comment: ESD-TRANSIL)
U34  value ESDALC6V1-1U2  [ESD_ST0201]  (hidden comment: ESD-TRANSIL)
U35  LD3985M33R  [REG_SOT23-5L]
X3  value NZ2520SH 25MHz  [OSC_NDK_NZ2520SB_4P]  (hidden comment: OSCILLATOR_4_PINS)

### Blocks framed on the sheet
ST-LINK POWER: C13-C16 C20-C25 C28-C33 C77 C84-C87 R52 U32
TAG CONNECTOR: CN10
ESD PROTECTIONS: U11 U12 U33 U34
LED STLK: LD3 R16 R17
STDC14 RECEIVER: CN9 R19 R22 R23 R58
5V ST-LINK PROTECTION: C52 C53 LD4 R31 R33 R36 U18
ST-LINK USB CONNECTOR: C47 CN8 U14 U15
ST-LINK POWER 3V3 / 150mA: C104-C106 C112 C113 D2-D4 U35

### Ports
NRST, T (harness T)

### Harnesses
T: SWCLK, SWDIO, SWO, JTDI, VCP_RX, VCP_TX, MCO

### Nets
3V3: CN9.3 CN10.1 R54.2
3V3_STLK: C13.1 C14.1 C15.1 C16.1 C21.1 C22.1 C23.1 C24.1 C25.1 C28.1 C29.1 C31.1 C32.1 C33.1 C77.1 C80.1 C84.2 C85.1 C86.2 C87.1 C104.2 C106.2 CN6.1 LD3.4(YellowGreen_anode) R53.1 U32.C1(VBAT) U32.C5(VDD) U32.C6(PDR_ON) U32.C7(VDD) U32.C8(VDD) U32.C9(VDD) U32.F3(VDD) U32.G3(VDD) U32.G13(VDD) U32.H13(VDD) U32.J12(VDD) U32.J13(VDD) U32.K4(VDD) U32.N8(VDD) U32.N9(VDD) U32.N10(VDD) U32.P1(VREF+) U32.R1(VDDA) U35.5(Vout) X3.4(VDD)
5V: R57.1
5V_UCPD: D3.1(A)
5V_USB_CHGR: C47.2 C53.2 CN8.1(VBUS) D4.1(A) R33.2 R36.2 U15.1(IO1) U18.5(IN)
5V_USB_STLK: C52.2 U18.1(OUT)
5V_VIN: D2.1(A)
GND: C13.2 C14.2 C15.2 C16.2 C20.1 C21.2 C22.2 C23.2 C24.2 C25.2 C28.2 C29.2 C30.1 C31.2 C32.2 C33.2 C47.1 C52.1 C53.1 C77.2 C79.2 C80.2 C81.2 C83.1 C84.1 C85.2 C86.1 C87.2 C104.1 C105.1 C106.1 C112.1 C113.1 CN6.3 CN8.5(GND) CN8.6(Shield) CN8.7(Shield) CN8.8(Shield) CN8.9(Shield) CN8.10(EXP) CN8.11(EXP) CN9.5 CN9.7 CN10.3 CN10.5 JP1.1(COMMON) LD3.1(RED_cathode) R31.1 R51.1 R52.1 R55.2 R56.1 R58.1 U11.2(GND) U12.2(GND) U14.3(GND) U15.2(GND) U18.2(GND) U32.D5(VSS) U32.D6(BOOT0) U32.D7(VSS) U32.D8(VSS) U32.D9(VSS) U32.F2(VSS) U32.F6(VSS) U32.F7(VSS) U32.F8(VSS) U32.F9(VSS) U32.F10(VSS) U32.F12(VSS) U32.G2(VSS) U32.G6(VSS) U32.G7(VSS) U32.G8(VSS) U32.G9(VSS) U32.G10(VSS) U32.G12(VSS) U32.H6(VSS) U32.H7(VSS) U32.H8(VSS) U32.H9(VSS) U32.H10(VSS) U32.H12(VSS) U32.J6(VSS) U32.J7(VSS) U32.J8(VSS) U32.J9(VSS) U32.J10(VSS) U32.K6(VSS) U32.K7(VSS) U32.K8(VSS) U32.K9(VSS) U32.K10(VSS) U32.M1(VSSA) U32.M8(VSS) U32.M9(VSS) U32.N1(VREF-) U33.2(GND) U34.2(GND) U35.2(GND) X3.2(GND)
GNDDetect: CN9.11 R58.2 U32.K13(GNDDetect/PG5)
LED_STLK: R16.2 R17.2 U32.D15(STLK_LED/PA10)
NRST: CN9.12 CN10.10 R22.1 U11.5(IO4) ; port NRST
STLK_SWCLK: CN6.2 U32.A14(STLK_SWCLK/PA14) U34.1(IO1)
STLK_SWDIO: CN6.4 U32.A15(STLK_SWDIO/PA13) U33.1(IO1)
STLK_VCP_RX: R18.2 U32.C10(STLK_VCP_RX/PG9)
STLK_VCP_TX: R19.1 U32.A7(STLK_VCP_TX/PG14)
T.JTDI: CN9.10 CN10.8 U12.1(IO1) ; port T.JTDI
T.MCO: C81.1 R49.2 ; port T.MCO
T.SWCLK: CN9.6 CN10.4 R23.1 U12.4(IO3) ; port T.SWCLK
T.SWDIO: CN9.4 CN10.2 R24.1 U12.5(IO4) ; port T.SWDIO
T.SWO: CN9.8 CN10.6 R20.1 U12.3(IO2) ; port T.SWO
T.VCP_RX: CN9.13 R19.2 U11.1(IO1) ; port T.VCP_RX
T.VCP_TX: CN9.14 R18.1 U11.3(IO2) ; port T.VCP_TX
T_NRSTa: R22.2 U32.P3(T_NRST/PA6)
T_PWR_EN: R31.2 U18.4(EN) U32.R5(T_PWR_EN/PB0)
T_PWR_EXT: R56.2 R57.2 U32.R4(T_PWR_EXT/PB1)
T_SWCLKa: R23.2 U32.M11(T_SWCLK/PH6)
T_SWDIO_IN: R25.2 U32.N12(T_SWDIO_IN/PH7)
T_SWDIOa: R24.2 R25.1 U32.L2(T_SWDIO_OUT/PF9)
T_SWOa: R20.2 U32.D12(T_SWO/PD2)
USB_DEV_HS_CN_N: CN8.2(DM) U14.5(D-)
USB_DEV_HS_CN_P: CN8.3(DP) U14.6(D+)
USB_DEV_HS_N: U14.2(D-) U32.R14(USB_DEV_HS_N/PB14)
USB_DEV_HS_P: U14.1(D+) U32.R15(USB_DEV_HS_P/PB15)
NetC20_2: C20.2 U32.F13(VCAP2)
NetC30_2: C30.2 U32.M10(VCAP1)
NetC79_1: C79.1 JP1.2(NO) U32.J1(NRST)
NetC83_2: C83.2 U32.J14(V12_OTGPHY)
NetC105_2: C105.2 U35.4(BYPASS)
NetC112_2: C112.2 C113.2 D2.2(K) D3.2(K) D4.2(K) U35.1(Vin) U35.3(CE)
NetLD3_2: LD3.2(Red_anode) R17.1
NetLD3_3: LD3.3(YellowGreen_cathode) R16.1
NetLD4_1: LD4.1 R33.1
NetLD4_2: LD4.2 R36.1 U18.3(~{FAULT})
NetR49_1: R49.1 U32.F15(STLK_MCO/PA8)
NetR50_1: R50.1 X3.3(OUT)
NetR50_2: R50.2 U32.G1(OSC_IN/PH0)
NetR51_2: R51.2 U32.J15(REXT_OTGPHY)
NetR52_2: R52.2 U32.L4(BYPASS-REG)
NetR53_2: R53.2 X3.1(EN)
NetR54_1: R54.1 R55.1 U32.N3(T_VCC_AIN/PA0)

Not connected (* = marked no-connect by the designer): CN8 4(ID)*; CN9 1* 2* 9*; CN10 7* 9*; U11 4(IO3)*; U14 4(NC)*; U32 C4(HW_TYP_1/PI5)* D4(HW_TYP_0/PI4)* H1(OSC_OUT/PH1)* R3(T_SW_DIR/PA7)*

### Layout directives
differential pair; rule Impedance Constraint [Min = 85.00    Max = 95.00    ]: USB_DEV_HS_CN_N, USB_DEV_HS_CN_P, USB_DEV_HS_N, USB_DEV_HS_P
rule Undefined; rule Matched Net Lengths [Tolerance = 2.5mm]; rule Impedance Constraint [Min = 85.00    Max = 95.00    ]: USB_DEV_HS_N
rule Undefined; rule Matched Net Lengths [Tolerance = 0.2mm]; rule Impedance Constraint [Min = 85.00    Max = 95.00    ]: USB_DEV_HS_CN_N, USB_DEV_HS_CN_P, USB_DEV_HS_P

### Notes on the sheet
- STLINK_MCU
- PA14
- PA13
- PB3
- PA15
- PA9
- LIMITATION :
  Some JTAG signals are multiplexed with UCPD: T_JTDI
  In case JTAG is plugged, UCPD signals can be disconnected.
  User need to check that multiplexed signals are not used on both features simultaneously.
- PA10
- PH0
- (near CN6) RSV
- Connector must be on the border of the PCB
- The routing of the tracks must be done on continuity from ST-LINK to 22ohm resistors and from resistors to Target MCU to avoid stub noises and EMC approach. (22ohm resistors must be very close to STDC14)
- (near CN6) 1
- level shifter 1V8/3V3
- HSE CLK STLINK
- (near JP1) STLK_NRST
- Ceramic capacitor (Low ESR)
- (near CN10) TAG
- COM
- (near CN10) TAG: Only footprint with cable: TC2050-IDC-NL
- Pin attributions on ESD can be swapped for layout optimisation
- (near R23) level shifter 1V8/3V3
- (near CN9) KEY
- (near R22) level shifter 1V8/3V3
- (near CN9) MIPI10
- (near R22) Specific constraints for T_SWDIO and T_SWCLK (must be same length and must be Shielded).
- (near LD4) STLK_OVC
- (near C47) Capacitor close to pin 1
- STLK

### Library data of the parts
C13-C16 C21-C25 C28 C29 C31-C33 C77 C79 C80 C85 C87 C104 C112 = MCD-00006: Capacitor, MLCC, 100nF, 16V, X7R, 10%, 0402, T=0.5mm; Manufacturer_Part_Number: CC0402KRX7R7BB104; Manufacturer: YAGEO; Provided_By: SUBCO; Initial_Board_Reference: MB1274
C20 C30 = MCD-00012: Capacitor, MLCC, 2.2uF, 10V, X5R, 10%, 0603, T=0,8mm; Manufacturer_Part_Number: CC0603KRX5R6BB225; Manufacturer: YAGEO; Alternate_Manufacturer_Part_Number: C0603C225K8PACTU; Alternate_Manufacturer: KEMET; Provided_By: SUBCO; Initial_Board_Reference: MB1274; Item Type: Item; Path: ws/MCD_ApplicationBoards/Lists/MCDPARTSdatabase
C47 = MCD-00205: Capacitor, MLCC, 100pF, 50V, NPO, 5%, 0402, T=0,5mm; Manufacturer_Part_Number: CC0402JRNPO9BN101; Manufacturer: YAGEO; Provided_By: Subcon; Initial_Board_Reference: MB1361
C52 C53 = MCD-00010: as C8 on sheet STMod+
C81 = MCD-00016: Capacitor, MLCC, 20pF, 50V, NPO, 5%, 0402, T=0,5mm; Manufacturer_Part_Number: CC0402JRNPO9BN200; Manufacturer: YAGEO; Provided_By: Subcon; Initial_Board_Reference: MB1274
C83 = MCD-00012: Capacitor, MLCC, 2.2uF, 10V, X5R, 10%, 0603, T=0,8mm; Manufacturer_Part_Number: CC0603KRX5R6BB225; Manufacturer: YAGEO; Alternate_Manufacturer_Part_Number: C0603C225K8PACTU; Alternate_Manufacturer: KEMET; Provided_By: Subcon; Initial_Board_Reference: MB1274
C84 C106 C113 = MCD-00010: Capacitor, MLCC, 1uF, 16V, X5R, 10%, 0603, T=0,8mm; Manufacturer_Part_Number: CC0603KRX5R7BB105; Manufacturer: YAGEO; Provided_By: Subcon; Initial_Board_Reference: MB1274
C86 = MCD-00009: as C62 on sheet MEMs
C105 = MCD-00011: Capacitor, MLCC, 10nF, 16V, X7R, 10%, 0402, T=0.5mm; Manufacturer_Part_Number: CC0402KRX7R7BB103; Manufacturer: YAGEO; Provided_By: Subcon; Initial_Board_Reference: MB1274
CN6 = MCD-00029: Header, 4x1, 2,54mm, VR, TH, Height 5.84mm/2.54mm; Manufacturer_Part_Number: TSW-104-07-x-S; Manufacturer: SAMTEC; Part_Type: Connector; Provided_By: Subcon; Initial_Board_Reference: MB1274
CN8 = MCD-00028: USB-MICRO-B, 0.65mm, RA, SMT, Bottom Mount,; Manufacturer_Part_Number: 1050170001; Manufacturer: MOLEX; Part_Type: Connector; Provided_By: Subcon; Initial_Board_Reference: MB1274
CN9 = MCD-01226: Header 5x2, 1.27mm, Dual row, Straight, Surface mount, vertical male connector. 3.05mm lead. Mates with FFSD connector. Footprint compatible with FTSH-107-01-L-DV,-K,-A,-P,-ES (STDC14 MEDIUM); Manufacturer_Part_Number: FTSH-105-01-L-DV-K; Manufacturer: SAMTEC; Provided_By: Subcon; Initial_Board_Reference: MCD16-052
CN10 = MCD-00031: Tag_Connector Header, 10x2, No legs; Manufacturer_Part_Number: TC2050-IDC-NL-FP; Manufacturer: TAG-CONNECT LLC; Provided_By: Subcon; Initial_Board_Reference: MB1274
D2-D4 = MCD-00034: Manufacturer: STMICROELECTRONICS; Part_Type: Diode; BMS_Part_Number: 9151097; Provided_By: Subcon; Initial_Board_Reference: MB1274
HW8 = MCD-00043: SHUNT 2.54mm BLACK; Manufacturer_Part_Number: SNT-100-BK-G; Manufacturer: SAMTEC; Part_Type: Mechanical; Provided_By: Subcon; Initial_Board_Reference: MB1274
JP1 = MCD-00045: Header, 2x1, 2,54mm, VR, TH, Height 5.84mm/2.54mm; Part_Type: Connector; Manufacturer_Part_Number: TSW-102-07-x-S; Manufacturer: SAMTEC; Value: Shunt not fitted; Provided_By: Subcon; Initial_Board_Reference: MB1274; Remark: 3D KO: BZ: 40098
LD3 = MCD-00051: LED Bicolor; Part_Type: Display; Manufacturer_Part_Number: HSMF-A201-A00J1; Manufacturer: AVAGO TECHNOLOGIES; Alternate_Manufacturer_Part_Number: LE-RGW35280; Alternate_Manufacturer: EVERLUCK; Provided_By: Subcon; Initial_Board_Reference: MB1274
LD4 = MCD-00049: LED, Red, 0603; Manufacturer_Part_Number: 19-213-R6C-AP1Q2B/3T; Manufacturer: EVERLIGHT; Part_Type: Display; Provided_By: Subcon; Initial_Board_Reference: MB1274
R16 R17 = MCD-00062: Resistor,330R,0402,1%,1/16W; Manufacturer_Part_Number: RC0402FR-07330RL; Manufacturer: YAGEO; Provided_By: SUBCO; Initial_Board_Reference: MB1274; Item Type: Item; Path: ws/MCD_ApplicationBoards/Lists/MCDPARTSdatabase
R18-R20 R22-R24 = MCD-00481: Resistor,47R,0402,1%,1/16W; Manufacturer_Part_Number: RC0402FR-0747RL; Manufacturer: YAGEO; Provided_By: SUBCO; Initial_Board_Reference: MBxxxx; Item Type: Item; Path: ws/MCD_ApplicationBoards/Lists/MCDPARTSdatabase
R25 R49 R50 R58 = MCD-00119: Resistor,100R,0402,1%,1/16W; Manufacturer_Part_Number: RC0402FR-07100RL; Manufacturer: YAGEO; Provided_By: Subcon; Initial_Board_Reference: MB1262
R31 = MCD-00053: Resistor,10K,0402,1%,1/16W; Manufacturer_Part_Number: RC0402FR-0710KL; Manufacturer: YAGEO; Provided_By: SUBCO; Initial_Board_Reference: MB1274; Item Type: Item; Path: ws/MCD_ApplicationBoards/Lists/MCDPARTSdatabase
R33 = MCD-00061: Resistor,1K,0402,1%,1/16W; Manufacturer_Part_Number: RC0402FR-071KL; Manufacturer: YAGEO; Provided_By: SUBCO; Initial_Board_Reference: MB1274; Item Type: Item; Path: ws/MCD_ApplicationBoards/Lists/MCDPARTSdatabase
R36 = MCD-00059: Resistor,100K,0402,1%,1/16W; Manufacturer_Part_Number: RC0402FR-07100KL; Manufacturer: YAGEO; Alternate_Manufacturer_Part_Number: RT0402FRE07100KL; Provided_By: SUBCO; Initial_Board_Reference: MB1274; Item Type: Item; Path: ws/MCD_ApplicationBoards/Lists/MCDPARTSdatabase
R51 = MCD-00185: Resistor,3K,0402,1%,1/16W; Manufacturer_Part_Number: RC0402FR-073KL; Manufacturer: YAGEO; Provided_By: Subcon
R52 R53 = MCD-00053: as R10 on sheet STMod+
R54-R56 = MCD-00065: Resistor,4K7,0402,1%,1/16W; Manufacturer_Part_Number: RC0402FR-074K7L; Manufacturer: YAGEO; Alternate_Manufacturer_Part_Number: RT0402FRE074K7L; Provided_By: Subcon; Initial_Board_Reference: MB1274
R57 = MCD-00055: Resistor,2K7,0402,1%,1/16W; Manufacturer_Part_Number: RC0402FR-072K7L; Manufacturer: YAGEO; Provided_By: Subcon; Initial_Board_Reference: MB1274
U11 U12 = MCD-00136: Dual Transil array for ESD protection; Part_Type: Diode; Manufacturer: STMICROELECTRONICS; BMS_Part_Number: 9151112; Provided_By: Subcon; Initial_Board_Reference: MB1262
U14 = MCD-00649: Common mode filter with ESD protection for USB 2.0 interface; Part_Type: Diode; Manufacturer: STMICROELECTRONICS; Provided_By: Subcon; Initial_Board_Reference: MB1248
U15 = MCD-01026: High power transient voltage suppressor; Part_Type: Diode; Manufacturer: STMICROELECTRONICS; Provided_By: SUBCO with ST control; Initial_Board_Reference: MB1378; Remark: Footprint moved fromROU lib: DFN105P160X60-2N to global-lib: ESD_QFN1610_2N_1K_2A; Item Type: Item; Path: ws/MCD_ApplicationBoards/Lists/MCDPARTSdatabase
U18 = MCD-00159: 500mA, Enhanced single channel power switches with active high enable pin; Part_Type: IC; Manufacturer: STMICROELECTRONICS; Alternate_Manufacturer_Part_Number: TPS2051C; Alternate_Manufacturer: TEXAS INSTRUMENTS; BMS_Part_Number: 9159009; Provided_By: Subcon; Initial_Board_Reference: MB1264
U32 = MCD-00596: STM32F723IEK  (STM32F7) BGA176; Part_Type: IC; Manufacturer_Part_Number: STM32F723IEK6; Manufacturer: STMICROELECTRONICS; BMS_Part_Number: 9175300; Provided_By: SUBCO with ST control; Initial_Board_Reference: MB1331; Item Type: Item; Path: ws/MCD_ApplicationBoards/Lists/MCDPARTSdatabase
U33 U34 = MCD-00170: ESD protection 6V1; Part_Type: Diode; Manufacturer: STMICROELECTRONICS; BMS_Part_Number: 9151132; Provided_By: Subcon; Initial_Board_Reference: MB1274
U35 = MCD-00086: Ultra low drop-low noise BiCMOS voltage, regulators low ESR capacitors compatible; Manufacturer: STMICROELECTRONICS; Part_Type: IC; BMS_Part_Number: 9176161; Provided_By: Subcon; Initial_Board_Reference: MB1274
X3 = MCD-00597: Oscillator 25Mhz, +-50ppm, Vcc:3.3V typ, square wave: [0.1Vcc;0.9Vcc], Enable pin, SMD; Part_Type: Crystal_Osc; Manufacturer_Part_Number: NZ2520SH 25MHz END4869C; Manufacturer: NDK; Alternate_Manufacturer_Part_Number: NZ2520SB 25MHz END4869B; BMS_Part_Number: 9157050; Provided_By: SUBCO

## Sheet WIFI&BT.SchDoc: WIFI&BT_INTERPOSERS
size A3; Author: P.A.; CompanyName: STMicroelectronics; Organization: Microcontrollers Division; Address1: 12, Rue Jules HOROWITZ; Address2: 38019 Grenoble; Address3: FRANCE; DocumentNumber: 13; Revision: C; SheetNumber: 13; SheetTotal: 16; Project: STM32L4S5AII6_IOT_V2; PageSetup: Record=PageOptions¦CenterHorizontal=True¦CenterVertical=True¦PrintScale=1.00¦XCorrection=1.00¦YCorrection=1.00¦PrintKind=1¦BorderSize=5000000¦LeftOffset=0¦BottomOffset=0¦Orientation=2¦PaperLength=1000¦PaperWidth=1000¦Scale=100¦PaperSource=7¦PrintQuality=-3¦MediaType=1¦DitherType=10¦PrintScaleMode=1¦PaperKind=Letter¦PaperIndex=1

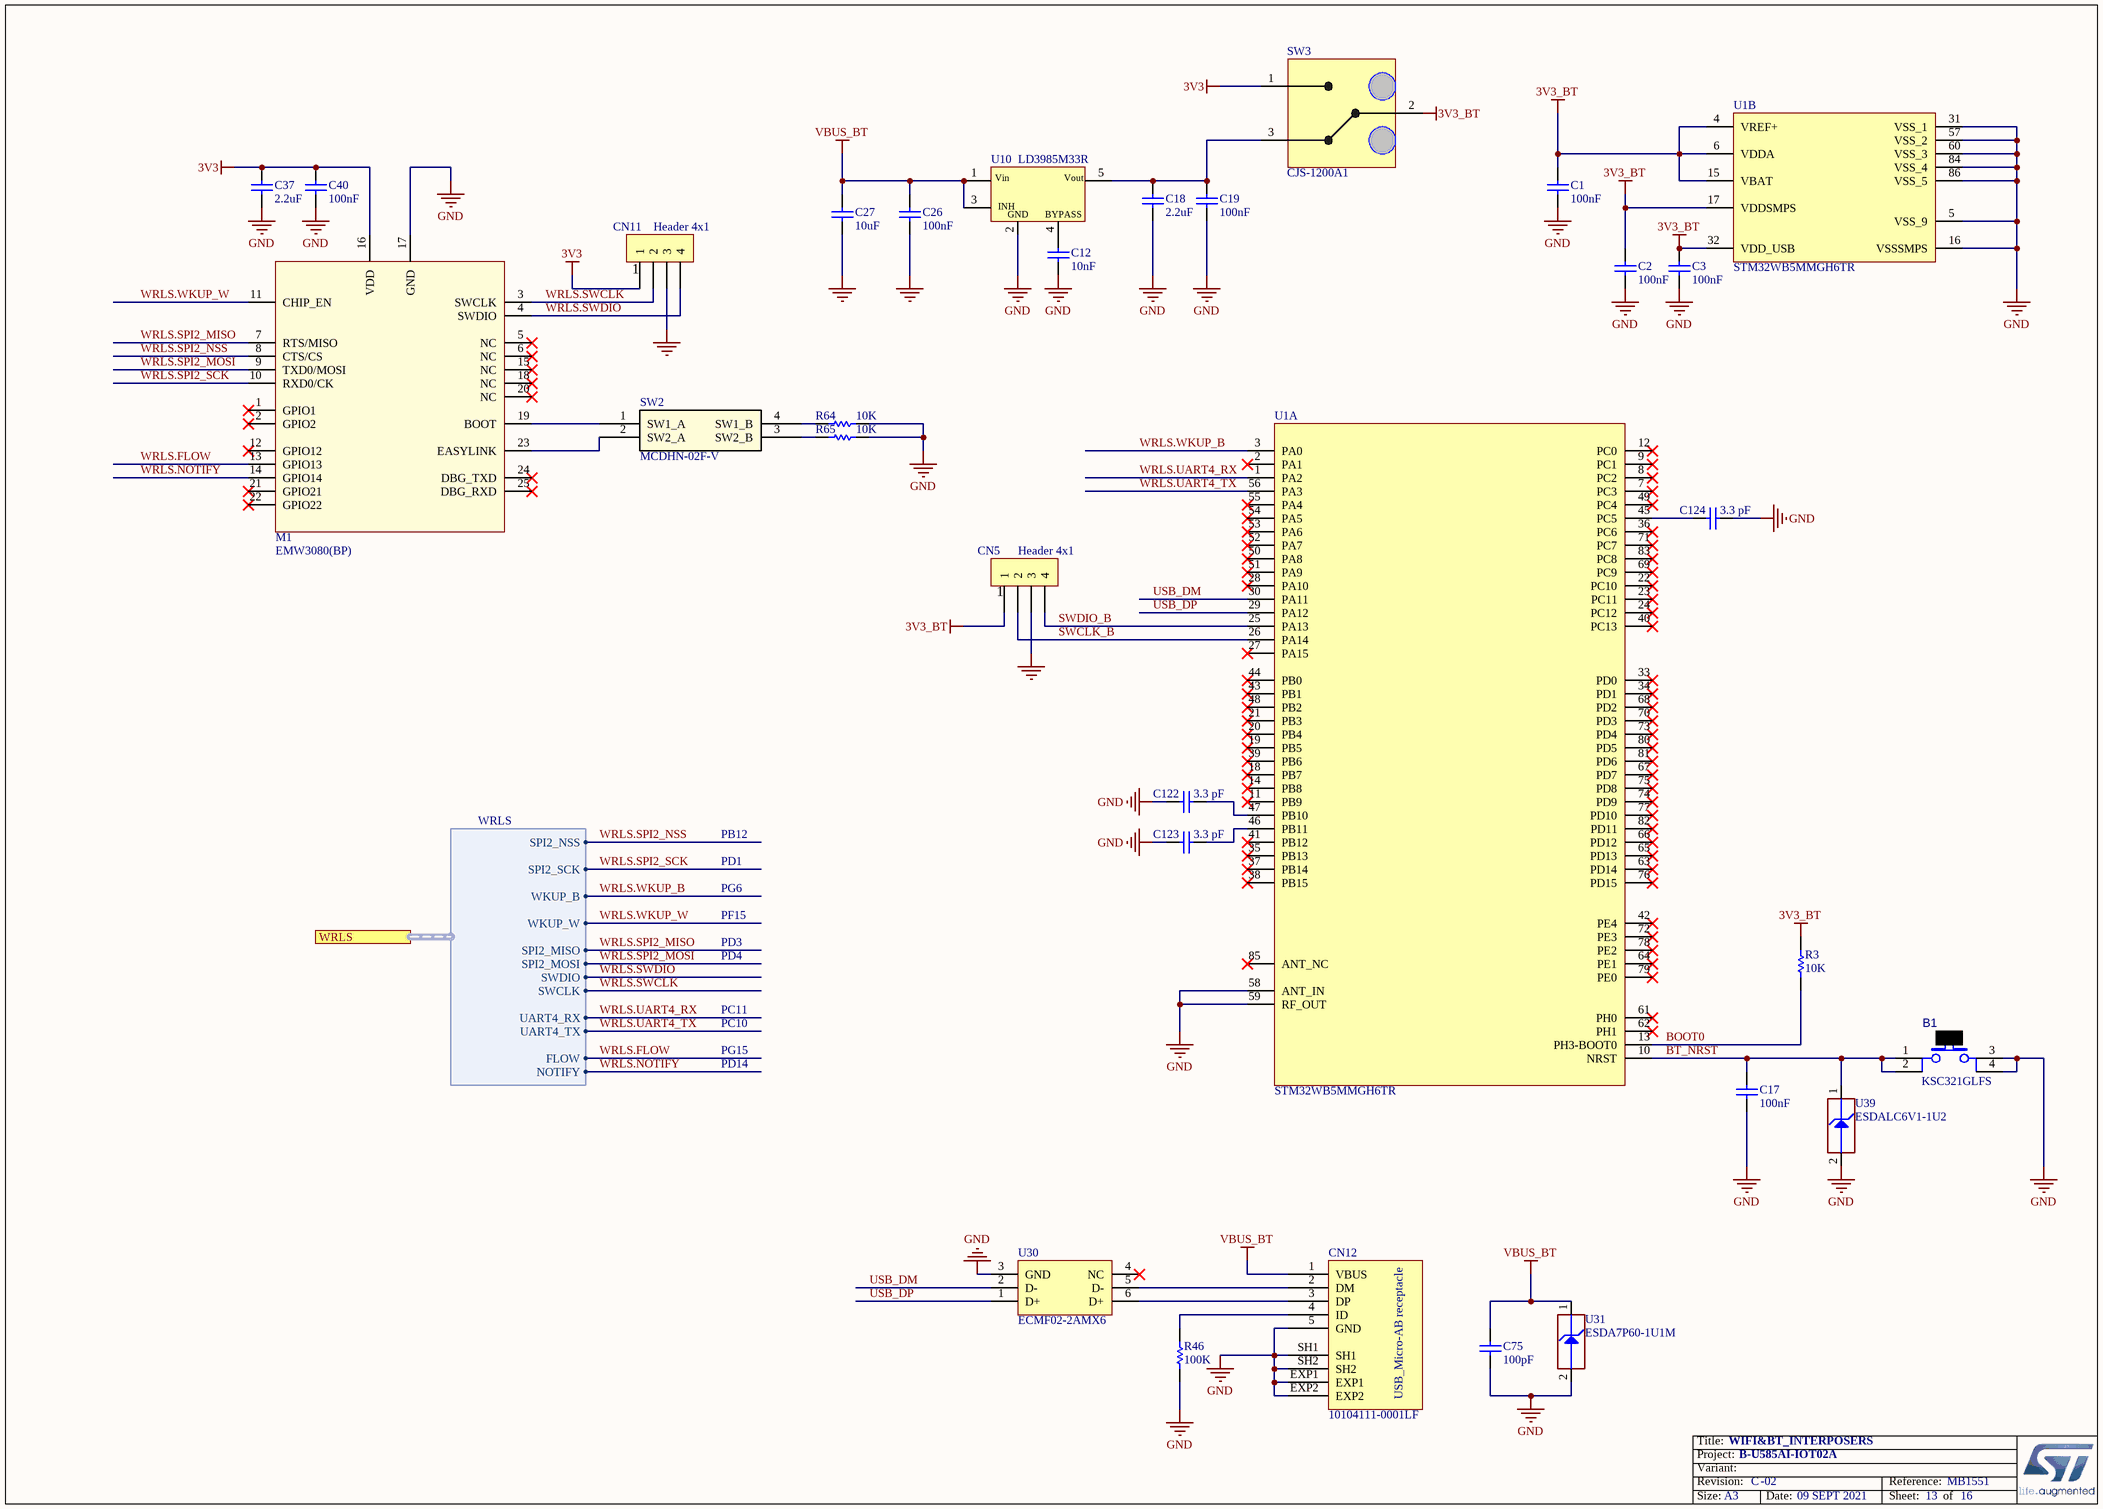
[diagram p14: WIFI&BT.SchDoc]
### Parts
B1  value KSC321GLFS  [SWI_C&K_KSC321GLFS_BLACK]  (hidden comment: SW_BLACK_KSC321GLFS)
C1  value 100nF  [C0402]
C2  value 100nF  [C0402]
C3  value 100nF  [C0402]
C12  value 10nF  [C0402]  (hidden comment: Capacitor)
C17  value 100nF  [C0402]
C18  value 2.2uF  [C0603]  (hidden comment: Capacitor)
C19  value 100nF  [C0402]  (hidden comment: Capacitor)
C26  value 100nF  [C0402]  (hidden comment: Capacitor)
C27  value 10uF  [C0603]  (hidden comment: Capacitor)
C37  value 2.2uF  [C0603]  (hidden comment: Capacitor)
C40  value 100nF  [C0402]  (hidden comment: Capacitor)
C75  value 100pF  [C0402]
C122  value 3.3 pF  [C0201_H0P3]  (hidden comment: Capacitor)
C123  value 3.3 pF  [C0201_H0P3]  (hidden comment: Capacitor)
C124  value 3.3 pF  [C0201_H0P3]  (hidden comment: Capacitor)
CN5  Header 4x1  [CON_SAMTEC_TSW-104-07-G-S]
CN11  Header 4x1  [CON_SAMTEC_TSW-104-07-G-S]
CN12  value 10104111-0001LF  [CON_USBMICROAB_FCI_10104111-0001LF]  (hidden comment: USB_uAB_10104111-0001LF)
M1  EMW3080(BP)  [MOD_WIFI_MXCHIP_EMW3080-BP]
R3  value 10K  [R0402]
R46  value 100K  [R0402]  (hidden comment: Resistor)
R64  value 10K  [R0603]
R65  value 10K  [R0603]
SW2  value MCDHN-02F-V  [SWI_MULTICOMP_MCDHN-02F-V_4P]  (hidden comment: SWITCH_2WAY)
SW3  CJS-1200A1  [SWI_CJS-1200A1]
U1  STM32WB5MMGH6TR  [MOD_DORY_STM_86P_7P3X11_H1P342]  (parts A,B of 2)
U10  LD3985M33R  [REG_SOT23-5L]
U30  ECMF02-2AMX6  [ESD_QFN-6L_1P7X1P5_P050]
U31  value ESDA7P60-1U1M  [ESD_QFN2_1P6X1_P125]  (hidden comment: ESD-TRANSIL)
U39  value ESDALC6V1-1U2  [ESD_ST0201]  (hidden comment: ESD-TRANSIL)

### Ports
WRLS (harness WRLS)

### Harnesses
WRLS: WKUP_B, WKUP_W, SPI2_NSS, SPI2_SCK, SPI2_MISO, SPI2_MOSI, SWDIO, SWCLK, UART4_RX, UART4_TX, FLOW, NOTIFY

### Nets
3V3: C37.2 C40.2 CN11.1 M1.16(VDD) SW3.1
3V3_BT: C1.2 C2.2 C3.2 CN5.1 R3.2 SW3.2 U1.4(VREF+) U1.6(VDDA) U1.15(VBAT) U1.17(VDDSMPS) U1.32(VDD_USB)
GND: B1.3 B1.4 C1.1 C2.1 C3.1 C12.2 C17.1 C18.1 C19.1 C26.1 C27.1 C37.1 C40.1 C75.1 C122.1 C123.1 C124.2 CN5.3 CN11.3 CN12.5(GND) CN12.EXP1 CN12.EXP2 CN12.SH1 CN12.SH2 M1.17(GND) R46.1 R64.2 R65.2 U1.5(VSS_9) U1.16(VSSSMPS) U1.31(VSS_1) U1.57(VSS_2) U1.58(ANT_IN) U1.59(RF_OUT) U1.60(VSS_3) U1.84(VSS_4) U1.86(VSS_5) U10.2(GND) U30.3(GND) U31.2(GND) U39.2(GND)
VBUS_BT: C26.2 C27.2 C75.2 CN12.1(VBUS) U10.1(Vin) U10.3(CE) U31.1(IO1)
BOOT0: R3.1 U1.13(PH3-BOOT0)
BT_NRST: B1.1 B1.2 C17.2 U1.10(NRST) U39.1(IO1)
SWCLK_B: CN5.2 U1.26(PA14)
SWDIO_B: CN5.4 U1.25(PA13)
USB_DM: U1.30(PA11) U30.2(D-)
USB_DP: U1.29(PA12) U30.1(D+)
WRLS.FLOW: M1.13(GPIO13) ; port WRLS.FLOW
WRLS.NOTIFY: M1.14(GPIO14) ; port WRLS.NOTIFY
WRLS.SPI2_MISO: M1.7(RTS/MISO) ; port WRLS.SPI2_MISO
WRLS.SPI2_MOSI: M1.9(TXD0/MOSI) ; port WRLS.SPI2_MOSI
WRLS.SPI2_NSS: M1.8(CTS/CS) ; port WRLS.SPI2_NSS
WRLS.SPI2_SCK: M1.10(RXD0/CK) ; port WRLS.SPI2_SCK
WRLS.SWCLK: CN11.2 M1.3(SWCLK) ; port WRLS.SWCLK
WRLS.SWDIO: CN11.4 M1.4(SWDIO) ; port WRLS.SWDIO
WRLS.UART4_RX: U1.1(PA2) ; port WRLS.UART4_RX
WRLS.UART4_TX: U1.56(PA3) ; port WRLS.UART4_TX
WRLS.WKUP_B: U1.3(PA0) ; port WRLS.WKUP_B
WRLS.WKUP_W: M1.11(CHIP_EN) ; port WRLS.WKUP_W
NetC12_1: C12.1 U10.4(BYPASS)
NetC18_2: C18.2 C19.2 SW3.3 U10.5(Vout)
NetC122_2: C122.2 U1.47(PB10)
NetC123_2: C123.2 U1.46(PB11)
NetC124_1: C124.1 U1.45(PC5)
NetCN12_2: CN12.2(DM) U30.5(D-)
NetCN12_3: CN12.3(DP) U30.6(D+)
NetCN12_4: CN12.4(ID) R46.2
NetM1_19: M1.19(BOOT) SW2.1(SW1_A)
NetM1_23: M1.23(EASYLINK) SW2.2(SW2_A)
NetR64_1: R64.1 SW2.4(SW1_B)
NetR65_1: R65.1 SW2.3(SW2_B)

Not connected (* = marked no-connect by the designer): M1 1(GPIO1)* 2(GPIO2)* 5(NC)* 6(NC)* 12(GPIO12)* 15(NC)* 18(NC)* 20(NC)* 21(GPIO21)* 22(GPIO22)* 24(DBG_TXD)* 25(DBG_RXD)*; U1 2(PA1)* 7(PC3)* 8(PC2)* 9(PC1)* 11(PB9)* 12(PC0)* 14(PB8)* 18(PB7)* 19(PB5)* 20(PB4)* 21(PB3)* 22(PC10)* 23(PC11)* 24(PC12)* 27(PA15)* 28(PA10)* 33(PD0)* 34(PD1)* 35(PB13)* 36(PC6)* 37(PB14)* 38(PB15)* 39(PB6)* 40(PC13)* 41(PB12)* 42(PE4)* 43(PB1)* 44(PB0)* 48(PB2)* 49(PC4)* 50(PA8)* 51(PA9)* 52(PA7)* 53(PA6)* 54(PA5)* 55(PA4)* 61(PH0)* 62(PH1)* 63(PD14)* 64(PE1)* 65(PD13)* 66(PD12)* 67(PD7)* 68(PD2)* 69(PC9)* 70(PD3)* 71(PC7)* 72(PE3)* 73(PD4)* 74(PD9)* 75(PD8)* 76(PD15)* 77(PD10)* 78(PE2)* 79(PE0)* 80(PD5)* 81(PD6)* 82(PD11)* 83(PC8)* 85(ANT_NC)*; U30 4(NC)*

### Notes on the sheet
- (near CN11) 1
- (near CN5) 1
- PB12
- PD1
- PF15
- PG6
- PD4
- PD3
- PC10
- PC11
- PG15
- PD14

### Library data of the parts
B1 = MCD-00175: Switch HW BLACK High3.5mm 2Newtons; Part_Type: Misc; Manufacturer: C&K; Provided_By: SUBCO; Initial_Board_Reference: MB1274
C1-C3 C17 = MCD-00006: as C119 on sheet OCTOSPI
C12 = MCD-00011: Capacitor,10nF,16V,X7R,10%,0402,YAGEO; Manufacturer_Part_Number: CC0402KRX7R7BB103; Provided_By: Subcon
C18 = MCD-00012: Capacitor,2.2uF,10V, X5R,10%,0603,YAGEO; Manufacturer_Part_Number: CC0603KRX5R6BB225; Alternate_Manufacturer_Part_Number: C0603C225K8PACTU; Alternate_Manufacturer: KEMET; Provided_By: Subcon
C19 C26 = MCD-00006: Capacitor,100nF,16V,X7R,10%,0402,YAGEO; Manufacturer_Part_Number: CC0402KRX7R7BB104; Provided_By: Subcon
C27 = MCD-00243: Capacitor,10uF,6V3,X5R,10%,0603,YAGEO; Manufacturer_Part_Number: CC0603KRX5R5BB106; Provided_By: Subcon
C37 = MCD-00012: Capacitor, MLCC, 2.2uF, 10V, X5R, 10%, 0603, T=0,8mm; Manufacturer_Part_Number: CC0603KRX5R6BB225; Manufacturer: YAGEO; Alternate_Manufacturer_Part_Number: C0603C225K8PACTU; Alternate_Manufacturer: KEMET; Provided_By: SUBCO
C40 = MCD-00006: Capacitor, MLCC, 100nF, 16V, X7R, 10%, 0402, T=0.5mm; Manufacturer_Part_Number: CC0402KRX7R7BB104; Manufacturer: YAGEO; Alternate_Manufacturer_Part_Number: GCM155R71C104KA55D; Alternate_Manufacturer: MURATA; ECCN_US: EAR99; ECCN_EU: NEC; Provided_By: SUBCO
C75 = MCD-00205: as C47 on sheet ST_LINK_V3E
C122-C124 = MCD-02284: Capacitor, MLCC, 3.3pF, 50V, NPO, +-0.05pF, 0201, T=0.3mm".; Part_Preference: Recommended; Manufacturer: MURATA; Manufacturer_Part_Number: GRM0335C2A3R3WA01J
CN5 CN11 = MCD-00029: as CN6 on sheet ST_LINK_V3E
CN12 = MCD-01075: USB, micro AB receptacle,10104111-0001LF; Part_Type: Connector; Manufacturer: FCI; Provided_By: SUBCO
M1 = MCD-01500: Wi-Fi module 33x18mm, UART-SPI interface; Part_Type: IC; Manufacturer: MXCHIP; Provided_By: SUBCO
R3 = MCD-00053: as R10 on sheet STMod+
R46 = MCD-00059: Resistor,100K,0402,1%,1/16W; Manufacturer_Part_Number: RC0402FR-07100KL; Manufacturer: YAGEO; Alternate_Manufacturer_Part_Number: RT0402FRE07100KL; ECCN_US: EAR99; ECCN_EU: NEC; Provided_By: SUBCO
R64 R65 = MCD-00220: as R12 on sheet OCTOSPI
SW2 = MCD-02105: DIP Switch Slide Type x2 poles 25mA 24VDC 100mR SMD; Part_Type: Misc; Manufacturer: MULTICOMP; Provided_By: SUBCO
SW3 = MCD-02279: SLIDE SWITCHE (SMD) serie CJS; Part_Preference: Recommended; Part_Type: Misc; Manufacturer: NIDEC Copal
U1 = MCD-01965: STM32 module BLE oriented  based on DORY STM32WB55; Part_Type: Misc; Manufacturer: STMICROELECTRONICS
U10 = MCD-00086: Ultra low drop-low noise BiCMOS voltage, regulators low ESR capacitors compatible; Manufacturer: STM; ECCN_US: EAR99; ECCN_EU: NEC
U30 = MCD-00649: Common mode filter with ESD protection for USB 2.0 interface; Part_Type: Diode; Manufacturer: STMICROELECTRONICS; BMS_Part_Number: 9151138; ECCN_US: EAR99; ECCN_EU: NEC; Provided_By: SUBCO with ST control
U31 = MCD-00251: High power transient voltage suppressor, 7V breakdown; Part_Type: Diode; Manufacturer: STMICROELECTRONICS; BMS_Part_Number: 9179042; ECCN_US: EAR99; ECCN_EU: NEC; Provided_By: SUBCO with ST control
U39 = MCD-00170: ESD protection 6V1; BMS_Part_Number: 9151132; Part_Preference: Recommended; Part_Type: Diode; Manufacturer: STMICROELECTRONICS

## Sheet USB_TYPEC.SchDoc: USB TYPE C
size A3; Date: Not used; ApprovedBy: Not used; CheckedBy: Not used; Author: Not used; CompanyName: STMicroelectronics; DrawnBy: Not used; Engineer: Not used; Organization: Not used; Address1: Not used; Address2: Not used; Address3: Not used; Address4: Not used; DocumentNumber: 9; Revision: Not used; SheetNumber: 9; SheetTotal: 16

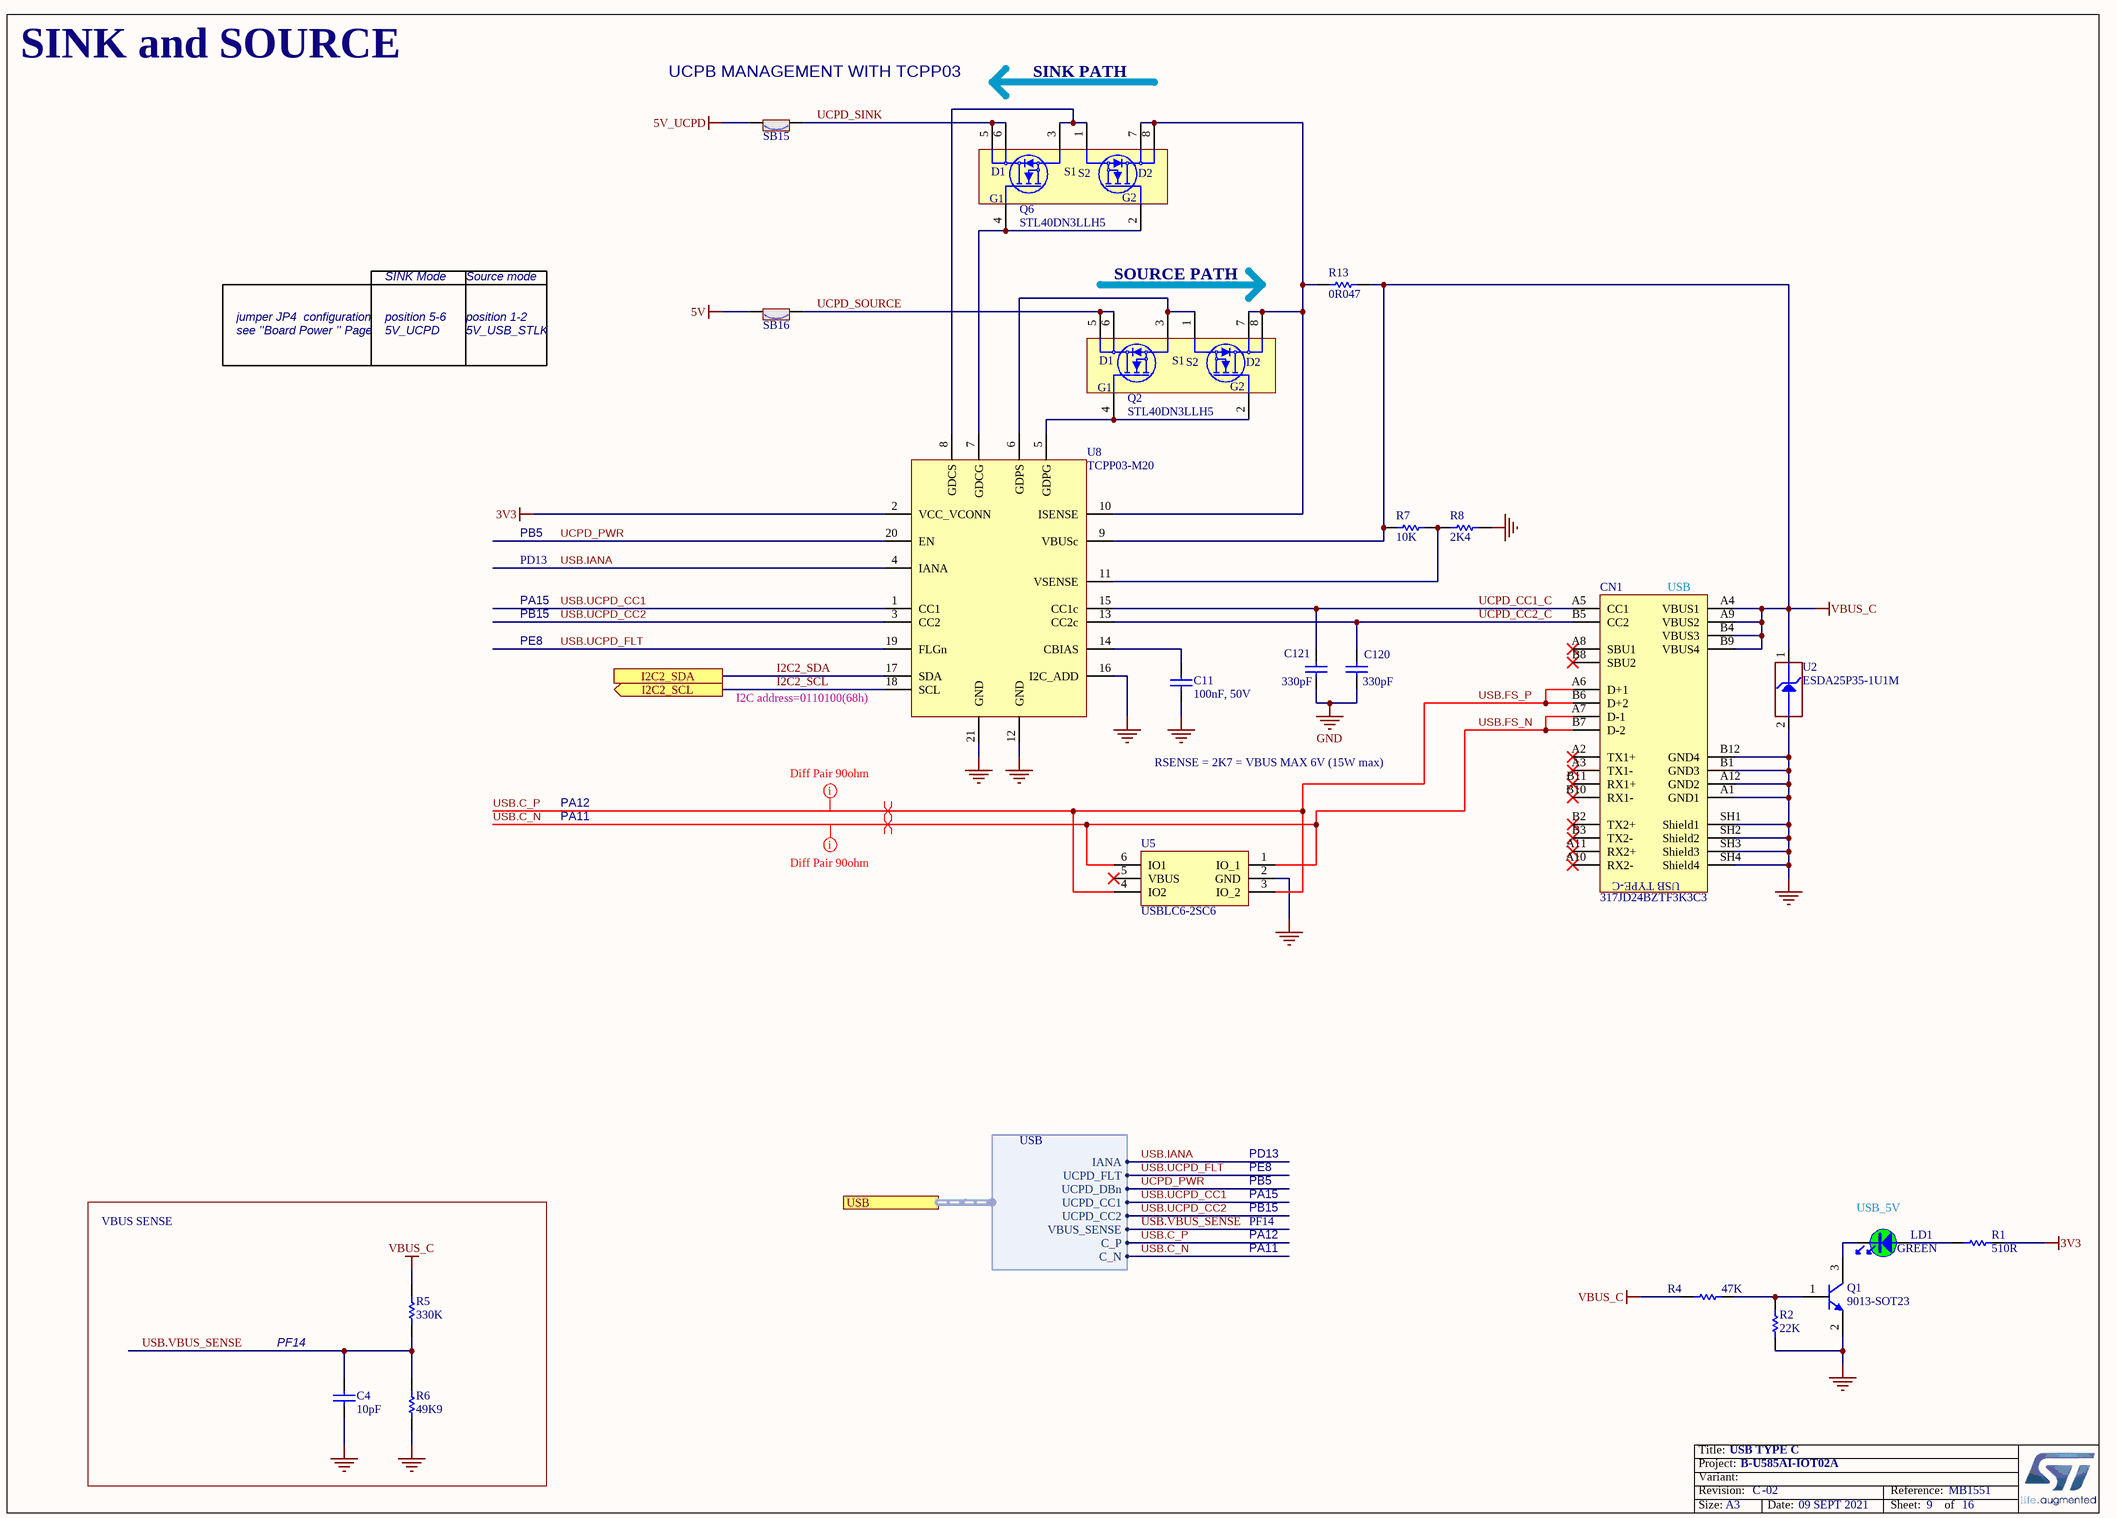
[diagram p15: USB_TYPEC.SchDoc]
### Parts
C4  value 10pF  [C0603]
C11  value 100nF, 50V  [C0603]
C120  value 330pF  [C0402]  (hidden comment: Capacitor)
C121  value 330pF  [C0402]  (hidden comment: Capacitor)
CN1  value 317JD24BZTF3K3C3  [CON_USB-TYPEC_COXOC_317JD24BZTF3K3C3]  (hidden comment: USB_TYPE_C_Receptacle_317JD24BZTF3K3C3)
LD1  value GREEN  [LED_0603_GREEN]
Q1  value 9013-SOT23  [NPN_SOT23]
Q2  STL40DN3LLH5  [PowerFLAT_5x6]
Q6  STL40DN3LLH5  [PowerFLAT_5x6]
R1  value 510R  [R0603]
R2  value 22K  [R0603]
R4  value 47K  [R0603]
R5  value 330K  [R0603]
R6  value 49K9  [R0603]
R7  value 10K  [R0603]
R8  value 2K4  [R0402]  (hidden comment: Resistor)
R13  value 0R047  [R0805_H0P5]  (hidden comment: Resistor)
SB15  (no value)  [SOLDER-BRIDGE_R0603-0R]
SB16  (no value)  [SOLDER-BRIDGE_R0603-0R]
U2  value ESDA25P35-1U1M  [ESD_QFN1610_2N_1K_2A]  (hidden comment: ESD-TRANSIL)
U5  USBLC6-2SC6  [ESD_SOT23-6L]
U8  TCPP03-M20  [ICC_QFN20-EPAD_4X4_P050]

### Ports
I2C2_SCL (out), I2C2_SDA, USB (harness USB)

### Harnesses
USB: UCPD_FLT, UCPD_DBn, UCPD_CC2, VBUS_SENSE, C_P, C_N, UCPD_CC1, IANA

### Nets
3V3: R1.1 U8.2(VCC_VCONN)
5V: SB16.2
5V_UCPD: SB15.2
GND: C4.1 C11.2 C120.1 C121.1 CN1.A1(GND1) CN1.A12(GND2) CN1.B1(GND3) CN1.B12(GND4) CN1.SH1(Shield1) CN1.SH2(Shield2) CN1.SH3(Shield3) CN1.SH4(Shield4) Q1.2(E) R2.1 R6.1 R8.2 U2.2(GND) U5.2(GND) U8.12(GND) U8.16(I2C_ADD) U8.21(GND)
VBUS_C: CN1.A4(VBUS1) CN1.A9(VBUS2) CN1.B4(VBUS3) CN1.B9(VBUS4) R4.1 R5.2 R7.2 R13.1 U2.1(IO1) U8.9(VBUSc)
I2C2_SCL: U8.18(SCL) ; port I2C2_SCL
I2C2_SDA: U8.17(SDA) ; port I2C2_SDA
UCPD_CC1_C: C121.2 CN1.A5(CC1) U8.15(CC1c)
UCPD_CC2_C: C120.2 CN1.B5(CC2) U8.13(CC2c)
UCPD_PWR: U8.20(EN) ; port USB.UCPD_DBn
UCPD_SINK: Q6.5(D1) Q6.6(D1) SB15.1
UCPD_SOURCE: Q2.5(D1) Q2.6(D1) SB16.1
USB.C_N: CN1.A7(D-1) CN1.B7(D-2) U5.1(IO_1) U5.6(IO1) ; port USB.C_N  [also labelled USB.FS_N]
USB.C_P: CN1.A6(D+1) CN1.B6(D+2) U5.3(IO_2) U5.4(IO2) ; port USB.C_P  [also labelled USB.FS_P]
USB.IANA: U8.4(IANA) ; port USB.IANA
USB.UCPD_CC1: U8.1(CC1) ; port USB.UCPD_CC1  [project net T.JTDI]
USB.UCPD_CC2: U8.3(CC2) ; port USB.UCPD_CC2
USB.UCPD_FLT: U8.19(FLGn) ; port USB.UCPD_FLT
USB.VBUS_SENSE: C4.2 R5.1 R6.2 ; port USB.VBUS_SENSE
NetC11_1: C11.1 U8.14(CBIAS)
NetLD1_1: LD1.1 R1.2
NetLD1_2: LD1.2 Q1.3(C)
NetQ1_1: Q1.1(B) R2.2 R4.2
NetQ2_1: Q2.1(S2) Q2.3(S1) U8.6(GDPS)
NetQ2_2: Q2.2(G2) Q2.4(G1) U8.5(GDPG)
NetQ2_7: Q2.7(D2) Q2.8(D2) Q6.7(D2) Q6.8(D2) R13.2 U8.10(ISENSE)
NetQ6_1: Q6.1(S2) Q6.3(S1) U8.8(GDCS)
NetQ6_2: Q6.2(G2) Q6.4(G1) U8.7(GDCG)
NetR7_1: R7.1 R8.1 U8.11(VSENSE)

Not connected (* = marked no-connect by the designer): CN1 A2(TX1+)* A3(TX1-)* A8(SBU1)* A10(RX2-)* A11(RX2+)* B2(TX2+)* B3(TX2-)* B8(SBU2)* B10(RX1-)* B11(RX1+)*; U5 5(VBUS)*

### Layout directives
mark named Diff Pair 90ohm: USB.C_N, USB.C_P
differential pair: USB.C_N, USB.C_P

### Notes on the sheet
- SINK and SOURCE
- (near SB15) UCPB MANAGEMENT WITH TCPP03
- SINK PATH
- jumper JP4  configuration
- position 5-6
- SINK Mode
- Source mode
- position 1-2
- SOURCE PATH
- see ''Board Power '' Page
- 5V_UCPD
- 5V_USB_STLK
- PB5
- PD13
- (near CN1) USB
- PA15
- PB15
- PE8
- (near U8) I2C address=0110100(68h)
- RSENSE = 2K7 = VBUS MAX 6V (15W max)
- PA12
- PA11
- VBUS SENSE
- PF14
- (near LD1) USB_5V

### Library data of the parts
C4 = MCD-00637: Capacitor, MLCC, 10pF, 50V, NPO, 5%, 0603, T=0,8mm; Manufacturer_Part_Number: CC0603JRNPO9BN100; Manufacturer: YAGEO; Provided_By: subcon; Initial_Board_Reference: MB1319
C11 = MCD-01099: Capacitor,100nF,50V,X7R,10%,0603; Manufacturer_Part_Number: CC0603KRX7R9BB104; Manufacturer: YAGEO; BMS_Part_Number: 9142278; Provided_By: SUBCO
C120 C121 = MCD-01579: Capacitor, MLCC, 330pF, 50V, NPO, +/-5%, 0402, T=0,5mm; Part_Preference: Recommended; Manufacturer: YAGEO; Manufacturer_Part_Number: CC0402JRNPO9BN331
CN1 = MCD-01108: USB tyce C certified receptacle for 1.6mm pcb height; Part_Type: Connector; Manufacturer: CHANT SINCERE (COXOC); Provided_By: SUBCO
LD1 = MCD-00050: LED, Green, 0603; Part_Type: Display; Manufacturer_Part_Number: 19-213SYGC/S530-E2/TR8; Manufacturer: EVERLIGHT; ECCN_US: EAR99; ECCN_EU: NEC; Provided_By: Subcon; Initial_Board_Reference: MB1274
Q1 = MCD-00073: NPN Bipolar Transistor; Part_Type: IC; Manufacturer_Part_Number: BSR14; Manufacturer: NXP; ECCN_US: EAR99; ECCN_EU: NEC; Provided_By: Subcon; Initial_Board_Reference: MB1274
Q2 Q6 = MCD-02152: Dual N-channel 30 V, 0.016 Ω typ., 40 A, STripFET™ H5 Power MOSFET; Part_Type: Transistor; Manufacturer: STMICROELECTRONICS; ECCN_US: EAR99; ECCN_EU: NEC; Provided_By: SUBCO
R1 = MCD-00225: Resistor,510R,0603,1%,1/10W; Manufacturer_Part_Number: RC0603FR-07510RL; Manufacturer: YAGEO; Provided_By: Subcon; Initial_Board_Reference: MB1319
R2 = MCD-00430: Resistor,22K,0603,1%,1/10W; Manufacturer_Part_Number: RC0603FR-0722KL; Manufacturer: YAGEO; Provided_By: Subcon
R4 = MCD-00222: Resistor,47K,0603,1%,1/10W; Manufacturer_Part_Number: RC0603FR-0747KL; Manufacturer: YAGEO; Provided_By: Subcon; Initial_Board_Reference: MB1319
R5 = MCD-00458: Resistor,330K,0603,1%,1/10W; Manufacturer_Part_Number: RC0603FR-07330KL; Manufacturer: YAGEO; Provided_By: Subcon
R6 = MCD-01171: Resistor,49K9,0603,1%; Manufacturer_Part_Number: RC0603FR-0749K9L; Manufacturer: YAGEO; Provided_By: Subcon; Initial_Board_Reference: MB1397
R7 = MCD-00220: as R12 on sheet OCTOSPI
R8 = MCD-00433: Resistor,2K4,0402,1%,1/16W; Part_Preference: Recommended; Manufacturer: YAGEO; Manufacturer_Part_Number: RC0402FR-072K4L
R13 = MCD-02151: Current Detection Resistor, 0R047, 0805, 1%, 1/4W; Manufacturer_Part_Number: RL0805FR-7W0R047L; Manufacturer: YAGEO; ECCN_US: NEC; ECCN_EU: EAR99; Provided_By: SUBCO
SB15 SB16 = MCD-00071: as SB17 on sheet MEMs
U2 = MCD-01207: High power Transient voltage suppressor:25V/35A EOS and ESD transients protection.; Part_Type: Diode; Manufacturer: STMICROELECTRONICS; BMS_Part_Number: 9179045; ECCN_US: EAR99; ECCN_EU: NEC; Provided_By: SUBCO with ST control
U5 = MCD-00163: Very low capacitance ESD protection; Part_Type: IC; Manufacturer: STMICROELECTRONICS; BMS_Part_Number: 9151075; ECCN_US: EAR99; ECCN_EU: NEC; Provided_By: SUBCO with ST control
U8 = MCD-02130: USB Type-C Port Protection for USB DRP Power Delivery, PPS compliant; Part_Type: IC; Manufacturer: STMICROELECTRONICS; ECCN_US: EAR99; ECCN_EU: NEC; Provided_By: SUBCO with ST control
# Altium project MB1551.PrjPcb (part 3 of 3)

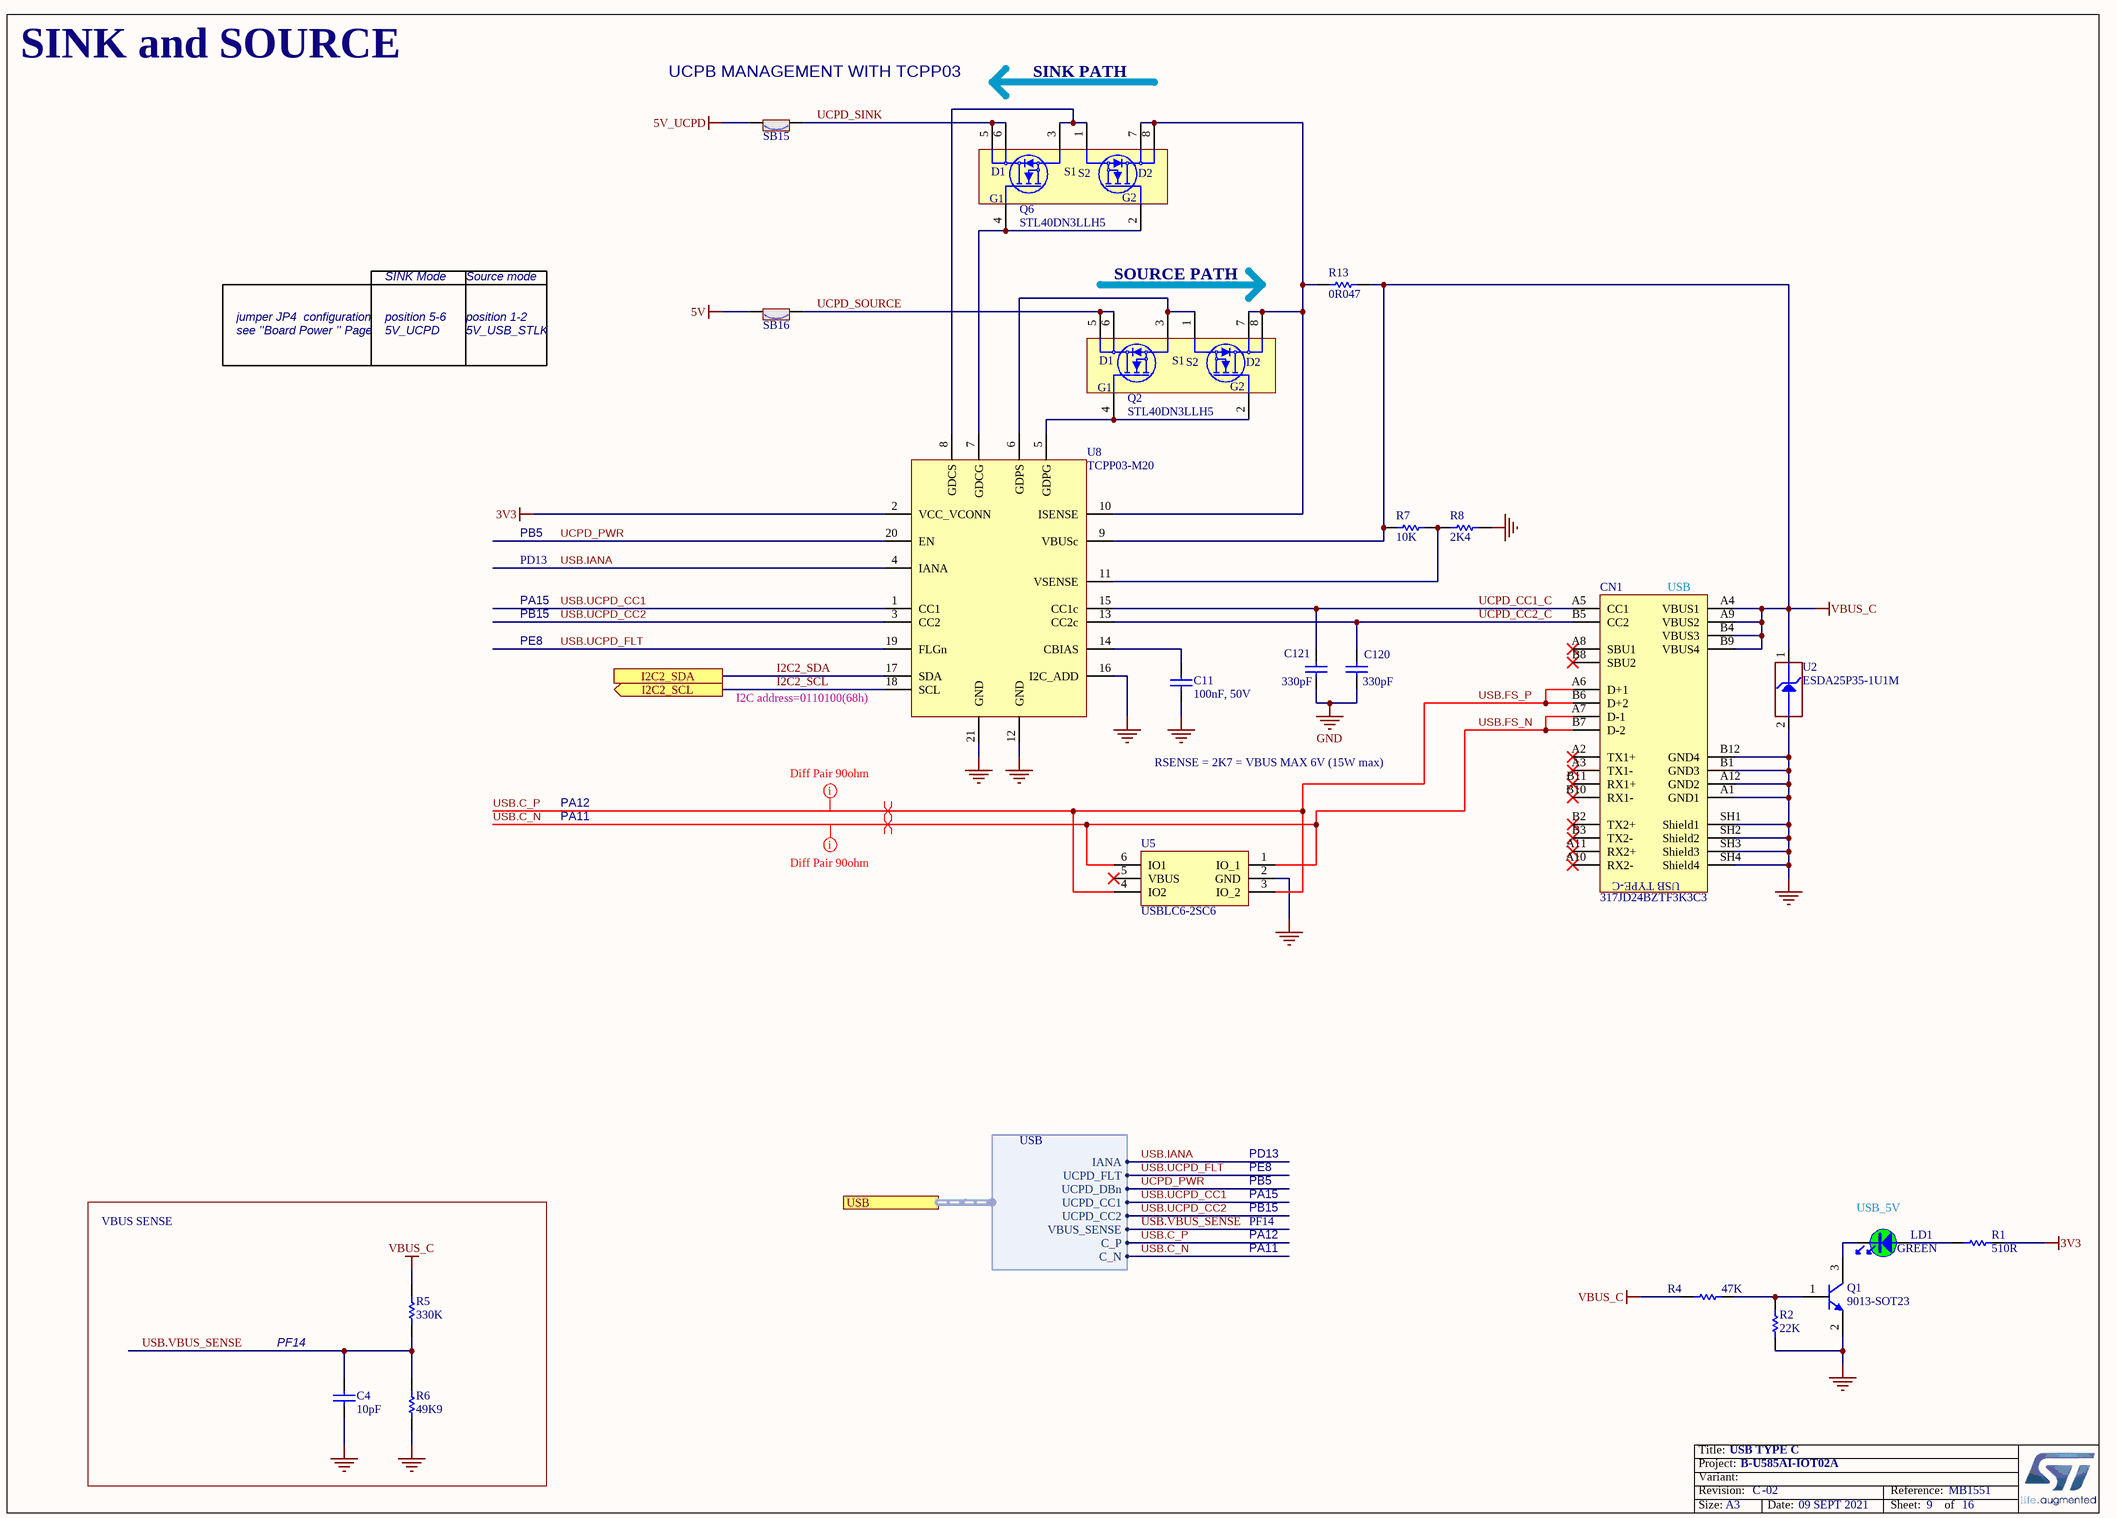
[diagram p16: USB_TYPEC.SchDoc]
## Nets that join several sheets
2V8: BOARD_PWR (SB9.2 TP12.1), Camera (8 pins)
3V3: ARDUINO (CN17.2 CN17.4 R9.1), AUDIO (7 pins), BOARD_PWR (5 pins), Camera (R32.2), MCU_CLOCK_&_RESET (5 pins), MEMs (39 pins), OCTOSPI (SB2.1 SB8.1), STMod+ (8 pins), ST_LINK_V3E (CN9.3 CN10.1 R54.2), WIFI&BT (5 pins), USB_TYPEC (R1.1 U8.2)
5V: ARDUINO (CN17.5), BOARD_PWR (10 pins), STMod+ (CN2.6 CN2.15 CN3.6 CN3.15), ST_LINK_V3E (R57.1), USB_TYPEC (SB16.2)
5V_UCPD: BOARD_PWR (JP4.5), ST_LINK_V3E (D3.1), USB_TYPEC (SB15.2)
5V_USB_CHGR: BOARD_PWR (JP4.7), ST_LINK_V3E (8 pins)
5V_USB_STLK: BOARD_PWR (JP4.1), ST_LINK_V3E (C52.2 U18.1)
5V_VIN: ARDUINO (R63.2), BOARD_PWR (C116.2 JP4.3 U38.2 U38.4), ST_LINK_V3E (D2.1)
GND: ARDUINO (5 pins), AUDIO (7 pins), BOARD_PWR (13 pins), Camera (15 pins), MCU_CLOCK_&_RESET (14 pins), MCU_PWR (38 pins), Mechanical_Parts (H1.1 H3.1 H4.1), MEMs (42 pins), OCTOSPI (15 pins), STMod+ (10 pins), ST_LINK_V3E (101 pins), WIFI&BT (41 pins), USB_TYPEC (21 pins)
VDD_MCU: BOARD_PWR (JP3.1), MCU_IO (R27.1 R28.1 R59.1 R60.1), MCU_PWR (37 pins)
VIN: ARDUINO (CN17.8), BOARD_PWR (C117.2 U38.3)
VREFP: ARDUINO (C74.1 R47.2), MCU_PWR (C38.1 C39.2 R21.2 U13.L1)
ARD.D0_RX: ARDUINO (CN14.1), MCU_IO (U13.L13), STMod+ (U3.7)
ARD.D1_TX: ARDUINO (CN14.2), MCU_IO (U13.L12), STMod+ (U3.4)
ARD.D2_IO: ARDUINO (CN14.3), MCU_IO (U13.J11)
ARD.D3_TIM: ARDUINO (CN14.4), MCU_IO (U13.L5)
ARD.D4_INT: ARDUINO (CN14.5), MCU_IO (U13.L7)
ARD.D5_TIM: ARDUINO (CN14.6), MCU_IO (U13.D4)
ARD.D6_TIM: ARDUINO (CN14.7), MCU_IO (U13.B5)
ARD.D7_IO: ARDUINO (CN14.8), MCU_IO (U13.M6)
ARD.D8_IO: ARDUINO (CN13.1), MCU_IO (U13.J3)
ARD.D9_TIM: ARDUINO (CN13.2), MCU_IO (U13.G7)
ARD.D10_TIM_SPI1_NSS: ARDUINO (CN13.3), MCU_IO (U13.N8)
ARD.D11_TIM_SPI1_MOSI: ARDUINO (CN13.4), MCU_IO (U13.M9), STMod+ (U4.6)
ARD.D12_SPI1_MISO: ARDUINO (CN13.5), MCU_IO (U13.K8), STMod+ (U4.9)
ARD.D13_SPI1_SCK: ARDUINO (CN13.6 R48.1), MCU_IO (U13.L8), STMod+ (U4.14)
ARD_ADC.A0: ARDUINO (CN16.1), MCU_IO (U13.J2)
ARD_ADC.A1: ARDUINO (CN16.2), MCU_IO (U13.J4)
ARD_ADC.A2: ARDUINO (CN16.3), MCU_IO (U13.L4)
ARD_ADC.A3: ARDUINO (CN16.4), MCU_IO (U13.M4)
ARD_ADC.A4: ARDUINO (SB10.1), MCU_IO (U13.J5)
ARD_ADC.A5: ARDUINO (SB13.1), MCU_IO (U13.K5)
CAM.D0: Camera (CN7.23), MCU_IO (U13.H13)
CAM.D1: Camera (CN7.24), MCU_IO (U13.G12)
CAM.D2: Camera (CN7.25), MCU_IO (U13.G10)
CAM.D3: Camera (CN7.26), MCU_IO (U13.C4)
CAM.D4: Camera (CN7.27), MCU_IO (U13.C11)
CAM.D5: Camera (CN7.28), MCU_IO (U13.B10)
CAM.D6: Camera (CN7.29), MCU_IO (U13.A2)
CAM.D7: Camera (CN7.30), MCU_IO (U13.C3)
CAM.HSYNC: Camera (CN7.31), MCU_IO (U13.D12)
CAM.PIXCLK: Camera (CN7.33), MCU_IO (U13.N4)
CAM.PLUG: Camera (CN7.15 R32.1), MCU_IO (U13.A12)
CAM.RSTI: Camera (CN7.17), MCU_IO (U13.D11)
CAM.VSYNC: Camera (CN7.32), MCU_IO (U13.F5)
CAM.XSDN: Camera (CN7.19), MCU_IO (U13.D10)
I2C1_SCL: ARDUINO (CN13.10 SB12.1), Camera (Q5.3 R30.1), MCU_IO (R59.2 U13.E5), STMod+ (CN3.7)
I2C1_SDA: ARDUINO (CN13.9 SB11.1), Camera (Q4.3 R26.1), MCU_IO (R60.2 U13.D5), STMod+ (CN3.10)
I2C2_SCL: MCU_IO (R28.2 U13.E10), MEMs (8 pins), STMod+ (CN2.7), USB_TYPEC (U8.18)
I2C2_SDA: MCU_IO (R27.2 U13.F9), MEMs (8 pins), STMod+ (CN2.10), USB_TYPEC (U8.17)
LED_GREEN: MCU_CLOCK_&_RESET (R42.2), MCU_IO (U13.F8)
LED_RED: MCU_CLOCK_&_RESET (R41.2), MCU_IO (U13.E11)
Mems.INT_IIS2MDC: MCU_IO (U13.K11), MEMs (U25.7)
Mems.INT_LPS22HH: MCU_IO (U13.K13), MEMs (U26.7)
Mems.ISM330DLC_INT1: MCU_IO (U13.M8), MEMs (U21.4)
Mems.STSAFE_RESET: MCU_IO (U13.M5), MEMs (U16.1)
Mems.VL53_xshut: MCU_IO (SB4.2), MEMs (U27.A5)
Mems.VLX_GPIO: MCU_IO (U13.J9), MEMs (R43.1 SB17.2 U27.A3)
MIC.CCK0: AUDIO (U6.4), MCU_IO (U13.J7)
MIC.CCK1: AUDIO (U7.4), MCU_IO (U13.H4)
MIC.SDIN0: AUDIO (U7.1), MCU_IO (U13.N5)
MIC.SDINx: AUDIO (U6.1), MCU_IO (U13.H8)
NRST: ARDUINO (CN17.3), MCU_CLOCK_&_RESET (B2.1 B2.2 C42.2 U23.1), MCU_IO (U13.H3), OCTOSPI (R14.1 R38.1), ST_LINK_V3E (CN9.12 CN10.10 R22.1 U11.5)
OCTOSPI.F_CLK_P: MCU_IO (U13.G6), OCTOSPI (U9.B2)
OCTOSPI.F_DQS: MCU_IO (U13.K6), OCTOSPI (U9.C3)
OCTOSPI.F_IO0: MCU_IO (U13.E2), OCTOSPI (U9.D3)
OCTOSPI.F_IO1: MCU_IO (U13.F3), OCTOSPI (U9.D2)
OCTOSPI.F_IO2: MCU_IO (U13.F4), OCTOSPI (U9.C4)
OCTOSPI.F_IO3: MCU_IO (U13.G5), OCTOSPI (U9.D4)
OCTOSPI.F_IO4: MCU_IO (U13.E9), OCTOSPI (U9.D5)
OCTOSPI.F_IO5: MCU_IO (U13.C13), OCTOSPI (U9.E3)
OCTOSPI.F_IO6: MCU_IO (U13.D9), OCTOSPI (U9.E2)
OCTOSPI.F_IO7: MCU_IO (U13.B13), OCTOSPI (U9.E1)
OCTOSPI.F_NCS: MCU_IO (U13.B3), OCTOSPI (R12.1 U9.C2)
OCTOSPI.R_CLK_P: MCU_IO (U13.K9), OCTOSPI (U20.B2 U37.6)
OCTOSPI.R_DQS: MCU_IO (U13.D3), OCTOSPI (U20.C3)
OCTOSPI.R_IO0: MCU_IO (U13.F1), OCTOSPI (U20.D3 U37.5)
OCTOSPI.R_IO1: MCU_IO (U13.G3), OCTOSPI (U20.D2 U37.2)
OCTOSPI.R_IO2: MCU_IO (U13.G2), OCTOSPI (U20.C4 U37.3)
OCTOSPI.R_IO3: MCU_IO (U13.H6), OCTOSPI (U20.D4 U37.7)
OCTOSPI.R_IO4: MCU_IO (U13.F10), OCTOSPI (U20.D5)
OCTOSPI.R_IO5: MCU_IO (U13.B12), OCTOSPI (U20.E3)
OCTOSPI.R_IO6: MCU_IO (U13.K1), OCTOSPI (U20.E2)
OCTOSPI.R_IO7: MCU_IO (U13.D7), OCTOSPI (U20.E1)
OCTOSPI.R_NCS: MCU_IO (U13.L9), OCTOSPI (R37.1 U20.A3 U37.1)
PC14-OSC32_IN: MCU_CLOCK_&_RESET (C46.1 X2.2), MCU_IO (U13.D1)
PC15-OSC32_OUT: MCU_CLOCK_&_RESET (C45.1 X2.1), MCU_IO (U13.E1)
PH0-OSC_IN: MCU_CLOCK_&_RESET (C44.1 X1.1), MCU_IO (SB5.1 U13.H1)
PH1-OSC_OUT: MCU_CLOCK_&_RESET (C41.1 X1.3), MCU_IO (SB4.1 U13.J1)
PH3-BOOT0: MCU_CLOCK_&_RESET (R35.2), MCU_IO (U13.C5)
STMOD+.1_17: MCU_IO (U13.A1), STMod+ (CN3.17)
STMOD+.1_18: MCU_IO (U13.B9), STMod+ (CN3.18)
STMOD+.1_19: MCU_IO (U13.G4), STMod+ (CN3.19)
STMOD+.1_20: MCU_IO (U13.M12), STMod+ (CN3.20)
STMOD+.1_ADC: MCU_IO (U13.K4), STMod+ (CN3.13)
STMOD+.1_INT: MCU_IO (U13.C2), STMod+ (CN3.11 CN4.7)
STMOD+.1_RST: MCU_IO (U13.G8), STMod+ (CN3.12 CN4.8)
STMOD+.1_SPI1_MISO_alt1: MCU_IO (U13.J8), STMod+ (CN3.9)
STMOD+.1_SPI1_MOSI_alt1: MCU_IO (U13.H11), STMod+ (CN3.8)
STMOD+.1_SPI1_NSS: MCU_IO (U13.N1), STMod+ (U4.1)
STMOD+.1_TIM: MCU_IO (U13.D2), STMod+ (CN3.14)
STMOD+.1_UART2_CTS: MCU_IO (U13.K3), STMod+ (U4.15)
STMOD+.1_UART2_RTS: MCU_IO (U13.L3), STMod+ (U4.12)
STMOD+.1_UART2_RX: MCU_IO (U13.N2), STMod+ (U4.7)
STMOD+.1_UART2_TX: MCU_IO (U13.M2), STMod+ (U4.4)
STMOD+.2_17: MCU_IO (U13.H7), STMod+ (CN2.17)
STMOD+.2_18: MCU_IO (U13.F7), STMod+ (CN2.18)
STMOD+.2_19: MCU_IO (U13.E7), STMod+ (CN2.19)
STMOD+.2_20: MCU_IO (U13.H9), STMod+ (CN2.20)
STMOD+.2_ADC: MCU_IO (U13.J6), STMod+ (CN2.13)
STMOD+.2_INT: MCU_IO (U13.E4), STMod+ (CN2.11)
STMOD+.2_RST: MCU_IO (U13.N13), STMod+ (CN2.12)
STMOD+.2_SPI3_MISO: MCU_IO (U13.C7), STMod+ (U3.9)
STMOD+.2_SPI3_MISO_alt1: MCU_IO (U13.B6), STMod+ (CN2.9)
STMOD+.2_SPI3_MOSI: MCU_IO (U13.B7), STMod+ (U3.6)
STMOD+.2_SPI3_MOSI_alt1: MCU_IO (U13.E8), STMod+ (CN2.8)
STMOD+.2_SPI3_NSS: MCU_IO (U13.E6), STMod+ (U3.1)
STMOD+.2_SPI3_SCK: MCU_IO (U13.A7), STMod+ (U3.14)
STMOD+.2_TIM: MCU_IO (U13.G9), STMod+ (CN2.14)
STMOD+.2_UART3_CTS: MCU_IO (U13.M13), STMod+ (U3.15)
STMOD+.2_UART3_RTS: MCU_IO (U13.K10), STMod+ (U3.12)
STMOD+.UART2_SPI1_SEL: MCU_IO (U13.C12), STMod+ (R11.1 U4.3 U4.10)
STMOD+.UART3_SPI3_SEL: MCU_IO (U13.A13), STMod+ (R10.1 U3.3 U3.10)
T.JTDI: MCU_IO (U13.A10), ST_LINK_V3E (CN9.10 CN10.8 U12.1), USB_TYPEC (U8.1)
T.MCO: MCU_IO (SB5.2), ST_LINK_V3E (C81.1 R49.2)
T.SWCLK: MCU_IO (U13.C10), ST_LINK_V3E (CN9.6 CN10.4 R23.1 U12.4)
T.SWDIO: MCU_IO (U13.F12), ST_LINK_V3E (CN9.4 CN10.2 R24.1 U12.5)
T.SWO: MCU_IO (U13.D6), ST_LINK_V3E (CN9.8 CN10.6 R20.1 U12.3)
T.VCP_RX: MCU_IO (U13.F11), ST_LINK_V3E (CN9.13 R19.2 U11.1)
T.VCP_TX: MCU_IO (U13.G11), ST_LINK_V3E (CN9.14 R18.1 U11.3)
UCPD_PWR: MCU_IO (U13.C6), USB_TYPEC (U8.20)
USB.C_N: MCU_IO (U13.G13), USB_TYPEC (CN1.A7 CN1.B7 U5.1 U5.6)
USB.C_P: MCU_IO (U13.F13), USB_TYPEC (CN1.A6 CN1.B6 U5.3 U5.4)
USB.IANA: MCU_IO (U13.K12), USB_TYPEC (U8.4)
USB.UCPD_CC2: MCU_IO (U13.L11), USB_TYPEC (U8.3)
USB.UCPD_FLT: MCU_IO (U13.K7), USB_TYPEC (U8.19)
USB.VBUS_SENSE: MCU_IO (U13.L6), USB_TYPEC (C4.2 R5.1 R6.2)
USER_BUTTON: MCU_CLOCK_&_RESET (C43.2 R39.1), MCU_IO (U13.E3)
WRLS.FLOW: MCU_IO (U13.A5), WIFI&BT (M1.13)
WRLS.NOTIFY: MCU_IO (U13.J10), WIFI&BT (M1.14)
WRLS.SPI2_MISO: MCU_IO (U13.D8), WIFI&BT (M1.7)
WRLS.SPI2_MOSI: MCU_IO (U13.C8), WIFI&BT (M1.9)
WRLS.SPI2_NSS: MCU_IO (U13.L10), WIFI&BT (M1.8)
WRLS.SPI2_SCK: MCU_IO (U13.F6), WIFI&BT (M1.10)
WRLS.UART4_RX: MCU_IO (U13.A9), WIFI&BT (U1.1)
WRLS.UART4_TX: MCU_IO (U13.C9), WIFI&BT (U1.56)
WRLS.WKUP_B: MCU_IO (U13.H10), WIFI&BT (U1.3)
WRLS.WKUP_W: MCU_IO (U13.N6), WIFI&BT (M1.11)

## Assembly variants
U585AI: not fitted C36 C41 C44 C48 C88 CN5 CN6 CN10 CN11 CN15 HW3 HW4 JP1 R3 R10 R11 R12 R15 R26 R30 R37 R47 R49 SB5 SB7 SB11 SB12 U37 X1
